# 
#              Synchronous High Speed Single Port SRAM Compiler 
# 
#                    UMC 0.18um GenericII Logic Process
#    __________________________________________________________________________
# 
# 
#      (C) Copyright 2002-2009 Faraday Technology Corp. All Rights Reserved.
#    
#    This source code is an unpublished work belongs to Faraday Technology
#    Corp.  It is considered a trade secret and is not to be divulged or
#    used by parties who have not received written authorization from
#    Faraday Technology Corp.
#    
#    Faraday's home page can be found at:
#    http://www.faraday-tech.com/
#   
#       Module Name      : SUMA180_2048X16X1BM1
#       Words            : 2048
#       Bits             : 16
#       Byte-Write       : 1
#       Aspect Ratio     : 1
#       Output Loading   : 0.05  (pf)
#       Data Slew        : 0.02  (ns)
#       CK Slew          : 0.02  (ns)
#       Power Ring Width : 2  (um)
# 
# -----------------------------------------------------------------------------
# 
#       Library          : FSA0M_A
#       Memaker          : 200901.2.1
#       Date             : 2025/11/09 15:44:09
# 
# -----------------------------------------------------------------------------


NAMESCASESENSITIVE ON ;
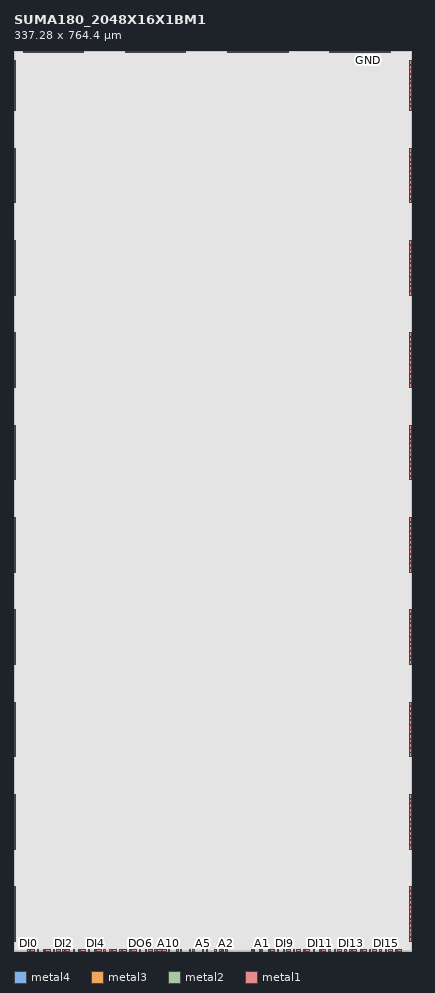
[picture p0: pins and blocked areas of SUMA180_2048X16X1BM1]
MACRO SUMA180_2048X16X1BM1
CLASS BLOCK ;
FOREIGN SUMA180_2048X16X1BM1 0.000 0.000 ;
ORIGIN 0.000 0.000 ;
SIZE 337.280 BY 764.400 ;
SYMMETRY x y r90 ;
SITE core_5040 ;
PIN VCC
  DIRECTION INOUT ;
  USE POWER ;
  SHAPE ABUTMENT ;
 PORT
  LAYER metal4 ;
  RECT 336.160 752.980 337.280 756.220 ;
  LAYER metal3 ;
  RECT 336.160 752.980 337.280 756.220 ;
  LAYER metal2 ;
  RECT 336.160 752.980 337.280 756.220 ;
  LAYER metal1 ;
  RECT 336.160 752.980 337.280 756.220 ;
 END
 PORT
  LAYER metal4 ;
  RECT 336.160 745.140 337.280 748.380 ;
  LAYER metal3 ;
  RECT 336.160 745.140 337.280 748.380 ;
  LAYER metal2 ;
  RECT 336.160 745.140 337.280 748.380 ;
  LAYER metal1 ;
  RECT 336.160 745.140 337.280 748.380 ;
 END
 PORT
  LAYER metal4 ;
  RECT 336.160 737.300 337.280 740.540 ;
  LAYER metal3 ;
  RECT 336.160 737.300 337.280 740.540 ;
  LAYER metal2 ;
  RECT 336.160 737.300 337.280 740.540 ;
  LAYER metal1 ;
  RECT 336.160 737.300 337.280 740.540 ;
 END
 PORT
  LAYER metal4 ;
  RECT 336.160 729.460 337.280 732.700 ;
  LAYER metal3 ;
  RECT 336.160 729.460 337.280 732.700 ;
  LAYER metal2 ;
  RECT 336.160 729.460 337.280 732.700 ;
  LAYER metal1 ;
  RECT 336.160 729.460 337.280 732.700 ;
 END
 PORT
  LAYER metal4 ;
  RECT 336.160 721.620 337.280 724.860 ;
  LAYER metal3 ;
  RECT 336.160 721.620 337.280 724.860 ;
  LAYER metal2 ;
  RECT 336.160 721.620 337.280 724.860 ;
  LAYER metal1 ;
  RECT 336.160 721.620 337.280 724.860 ;
 END
 PORT
  LAYER metal4 ;
  RECT 336.160 713.780 337.280 717.020 ;
  LAYER metal3 ;
  RECT 336.160 713.780 337.280 717.020 ;
  LAYER metal2 ;
  RECT 336.160 713.780 337.280 717.020 ;
  LAYER metal1 ;
  RECT 336.160 713.780 337.280 717.020 ;
 END
 PORT
  LAYER metal4 ;
  RECT 336.160 674.580 337.280 677.820 ;
  LAYER metal3 ;
  RECT 336.160 674.580 337.280 677.820 ;
  LAYER metal2 ;
  RECT 336.160 674.580 337.280 677.820 ;
  LAYER metal1 ;
  RECT 336.160 674.580 337.280 677.820 ;
 END
 PORT
  LAYER metal4 ;
  RECT 336.160 666.740 337.280 669.980 ;
  LAYER metal3 ;
  RECT 336.160 666.740 337.280 669.980 ;
  LAYER metal2 ;
  RECT 336.160 666.740 337.280 669.980 ;
  LAYER metal1 ;
  RECT 336.160 666.740 337.280 669.980 ;
 END
 PORT
  LAYER metal4 ;
  RECT 336.160 658.900 337.280 662.140 ;
  LAYER metal3 ;
  RECT 336.160 658.900 337.280 662.140 ;
  LAYER metal2 ;
  RECT 336.160 658.900 337.280 662.140 ;
  LAYER metal1 ;
  RECT 336.160 658.900 337.280 662.140 ;
 END
 PORT
  LAYER metal4 ;
  RECT 336.160 651.060 337.280 654.300 ;
  LAYER metal3 ;
  RECT 336.160 651.060 337.280 654.300 ;
  LAYER metal2 ;
  RECT 336.160 651.060 337.280 654.300 ;
  LAYER metal1 ;
  RECT 336.160 651.060 337.280 654.300 ;
 END
 PORT
  LAYER metal4 ;
  RECT 336.160 643.220 337.280 646.460 ;
  LAYER metal3 ;
  RECT 336.160 643.220 337.280 646.460 ;
  LAYER metal2 ;
  RECT 336.160 643.220 337.280 646.460 ;
  LAYER metal1 ;
  RECT 336.160 643.220 337.280 646.460 ;
 END
 PORT
  LAYER metal4 ;
  RECT 336.160 635.380 337.280 638.620 ;
  LAYER metal3 ;
  RECT 336.160 635.380 337.280 638.620 ;
  LAYER metal2 ;
  RECT 336.160 635.380 337.280 638.620 ;
  LAYER metal1 ;
  RECT 336.160 635.380 337.280 638.620 ;
 END
 PORT
  LAYER metal4 ;
  RECT 336.160 596.180 337.280 599.420 ;
  LAYER metal3 ;
  RECT 336.160 596.180 337.280 599.420 ;
  LAYER metal2 ;
  RECT 336.160 596.180 337.280 599.420 ;
  LAYER metal1 ;
  RECT 336.160 596.180 337.280 599.420 ;
 END
 PORT
  LAYER metal4 ;
  RECT 336.160 588.340 337.280 591.580 ;
  LAYER metal3 ;
  RECT 336.160 588.340 337.280 591.580 ;
  LAYER metal2 ;
  RECT 336.160 588.340 337.280 591.580 ;
  LAYER metal1 ;
  RECT 336.160 588.340 337.280 591.580 ;
 END
 PORT
  LAYER metal4 ;
  RECT 336.160 580.500 337.280 583.740 ;
  LAYER metal3 ;
  RECT 336.160 580.500 337.280 583.740 ;
  LAYER metal2 ;
  RECT 336.160 580.500 337.280 583.740 ;
  LAYER metal1 ;
  RECT 336.160 580.500 337.280 583.740 ;
 END
 PORT
  LAYER metal4 ;
  RECT 336.160 572.660 337.280 575.900 ;
  LAYER metal3 ;
  RECT 336.160 572.660 337.280 575.900 ;
  LAYER metal2 ;
  RECT 336.160 572.660 337.280 575.900 ;
  LAYER metal1 ;
  RECT 336.160 572.660 337.280 575.900 ;
 END
 PORT
  LAYER metal4 ;
  RECT 336.160 564.820 337.280 568.060 ;
  LAYER metal3 ;
  RECT 336.160 564.820 337.280 568.060 ;
  LAYER metal2 ;
  RECT 336.160 564.820 337.280 568.060 ;
  LAYER metal1 ;
  RECT 336.160 564.820 337.280 568.060 ;
 END
 PORT
  LAYER metal4 ;
  RECT 336.160 556.980 337.280 560.220 ;
  LAYER metal3 ;
  RECT 336.160 556.980 337.280 560.220 ;
  LAYER metal2 ;
  RECT 336.160 556.980 337.280 560.220 ;
  LAYER metal1 ;
  RECT 336.160 556.980 337.280 560.220 ;
 END
 PORT
  LAYER metal4 ;
  RECT 336.160 517.780 337.280 521.020 ;
  LAYER metal3 ;
  RECT 336.160 517.780 337.280 521.020 ;
  LAYER metal2 ;
  RECT 336.160 517.780 337.280 521.020 ;
  LAYER metal1 ;
  RECT 336.160 517.780 337.280 521.020 ;
 END
 PORT
  LAYER metal4 ;
  RECT 336.160 509.940 337.280 513.180 ;
  LAYER metal3 ;
  RECT 336.160 509.940 337.280 513.180 ;
  LAYER metal2 ;
  RECT 336.160 509.940 337.280 513.180 ;
  LAYER metal1 ;
  RECT 336.160 509.940 337.280 513.180 ;
 END
 PORT
  LAYER metal4 ;
  RECT 336.160 502.100 337.280 505.340 ;
  LAYER metal3 ;
  RECT 336.160 502.100 337.280 505.340 ;
  LAYER metal2 ;
  RECT 336.160 502.100 337.280 505.340 ;
  LAYER metal1 ;
  RECT 336.160 502.100 337.280 505.340 ;
 END
 PORT
  LAYER metal4 ;
  RECT 336.160 494.260 337.280 497.500 ;
  LAYER metal3 ;
  RECT 336.160 494.260 337.280 497.500 ;
  LAYER metal2 ;
  RECT 336.160 494.260 337.280 497.500 ;
  LAYER metal1 ;
  RECT 336.160 494.260 337.280 497.500 ;
 END
 PORT
  LAYER metal4 ;
  RECT 336.160 486.420 337.280 489.660 ;
  LAYER metal3 ;
  RECT 336.160 486.420 337.280 489.660 ;
  LAYER metal2 ;
  RECT 336.160 486.420 337.280 489.660 ;
  LAYER metal1 ;
  RECT 336.160 486.420 337.280 489.660 ;
 END
 PORT
  LAYER metal4 ;
  RECT 336.160 478.580 337.280 481.820 ;
  LAYER metal3 ;
  RECT 336.160 478.580 337.280 481.820 ;
  LAYER metal2 ;
  RECT 336.160 478.580 337.280 481.820 ;
  LAYER metal1 ;
  RECT 336.160 478.580 337.280 481.820 ;
 END
 PORT
  LAYER metal4 ;
  RECT 336.160 439.380 337.280 442.620 ;
  LAYER metal3 ;
  RECT 336.160 439.380 337.280 442.620 ;
  LAYER metal2 ;
  RECT 336.160 439.380 337.280 442.620 ;
  LAYER metal1 ;
  RECT 336.160 439.380 337.280 442.620 ;
 END
 PORT
  LAYER metal4 ;
  RECT 336.160 431.540 337.280 434.780 ;
  LAYER metal3 ;
  RECT 336.160 431.540 337.280 434.780 ;
  LAYER metal2 ;
  RECT 336.160 431.540 337.280 434.780 ;
  LAYER metal1 ;
  RECT 336.160 431.540 337.280 434.780 ;
 END
 PORT
  LAYER metal4 ;
  RECT 336.160 423.700 337.280 426.940 ;
  LAYER metal3 ;
  RECT 336.160 423.700 337.280 426.940 ;
  LAYER metal2 ;
  RECT 336.160 423.700 337.280 426.940 ;
  LAYER metal1 ;
  RECT 336.160 423.700 337.280 426.940 ;
 END
 PORT
  LAYER metal4 ;
  RECT 336.160 415.860 337.280 419.100 ;
  LAYER metal3 ;
  RECT 336.160 415.860 337.280 419.100 ;
  LAYER metal2 ;
  RECT 336.160 415.860 337.280 419.100 ;
  LAYER metal1 ;
  RECT 336.160 415.860 337.280 419.100 ;
 END
 PORT
  LAYER metal4 ;
  RECT 336.160 408.020 337.280 411.260 ;
  LAYER metal3 ;
  RECT 336.160 408.020 337.280 411.260 ;
  LAYER metal2 ;
  RECT 336.160 408.020 337.280 411.260 ;
  LAYER metal1 ;
  RECT 336.160 408.020 337.280 411.260 ;
 END
 PORT
  LAYER metal4 ;
  RECT 336.160 400.180 337.280 403.420 ;
  LAYER metal3 ;
  RECT 336.160 400.180 337.280 403.420 ;
  LAYER metal2 ;
  RECT 336.160 400.180 337.280 403.420 ;
  LAYER metal1 ;
  RECT 336.160 400.180 337.280 403.420 ;
 END
 PORT
  LAYER metal4 ;
  RECT 336.160 360.980 337.280 364.220 ;
  LAYER metal3 ;
  RECT 336.160 360.980 337.280 364.220 ;
  LAYER metal2 ;
  RECT 336.160 360.980 337.280 364.220 ;
  LAYER metal1 ;
  RECT 336.160 360.980 337.280 364.220 ;
 END
 PORT
  LAYER metal4 ;
  RECT 336.160 353.140 337.280 356.380 ;
  LAYER metal3 ;
  RECT 336.160 353.140 337.280 356.380 ;
  LAYER metal2 ;
  RECT 336.160 353.140 337.280 356.380 ;
  LAYER metal1 ;
  RECT 336.160 353.140 337.280 356.380 ;
 END
 PORT
  LAYER metal4 ;
  RECT 336.160 345.300 337.280 348.540 ;
  LAYER metal3 ;
  RECT 336.160 345.300 337.280 348.540 ;
  LAYER metal2 ;
  RECT 336.160 345.300 337.280 348.540 ;
  LAYER metal1 ;
  RECT 336.160 345.300 337.280 348.540 ;
 END
 PORT
  LAYER metal4 ;
  RECT 336.160 337.460 337.280 340.700 ;
  LAYER metal3 ;
  RECT 336.160 337.460 337.280 340.700 ;
  LAYER metal2 ;
  RECT 336.160 337.460 337.280 340.700 ;
  LAYER metal1 ;
  RECT 336.160 337.460 337.280 340.700 ;
 END
 PORT
  LAYER metal4 ;
  RECT 336.160 329.620 337.280 332.860 ;
  LAYER metal3 ;
  RECT 336.160 329.620 337.280 332.860 ;
  LAYER metal2 ;
  RECT 336.160 329.620 337.280 332.860 ;
  LAYER metal1 ;
  RECT 336.160 329.620 337.280 332.860 ;
 END
 PORT
  LAYER metal4 ;
  RECT 336.160 321.780 337.280 325.020 ;
  LAYER metal3 ;
  RECT 336.160 321.780 337.280 325.020 ;
  LAYER metal2 ;
  RECT 336.160 321.780 337.280 325.020 ;
  LAYER metal1 ;
  RECT 336.160 321.780 337.280 325.020 ;
 END
 PORT
  LAYER metal4 ;
  RECT 336.160 282.580 337.280 285.820 ;
  LAYER metal3 ;
  RECT 336.160 282.580 337.280 285.820 ;
  LAYER metal2 ;
  RECT 336.160 282.580 337.280 285.820 ;
  LAYER metal1 ;
  RECT 336.160 282.580 337.280 285.820 ;
 END
 PORT
  LAYER metal4 ;
  RECT 336.160 274.740 337.280 277.980 ;
  LAYER metal3 ;
  RECT 336.160 274.740 337.280 277.980 ;
  LAYER metal2 ;
  RECT 336.160 274.740 337.280 277.980 ;
  LAYER metal1 ;
  RECT 336.160 274.740 337.280 277.980 ;
 END
 PORT
  LAYER metal4 ;
  RECT 336.160 266.900 337.280 270.140 ;
  LAYER metal3 ;
  RECT 336.160 266.900 337.280 270.140 ;
  LAYER metal2 ;
  RECT 336.160 266.900 337.280 270.140 ;
  LAYER metal1 ;
  RECT 336.160 266.900 337.280 270.140 ;
 END
 PORT
  LAYER metal4 ;
  RECT 336.160 259.060 337.280 262.300 ;
  LAYER metal3 ;
  RECT 336.160 259.060 337.280 262.300 ;
  LAYER metal2 ;
  RECT 336.160 259.060 337.280 262.300 ;
  LAYER metal1 ;
  RECT 336.160 259.060 337.280 262.300 ;
 END
 PORT
  LAYER metal4 ;
  RECT 336.160 251.220 337.280 254.460 ;
  LAYER metal3 ;
  RECT 336.160 251.220 337.280 254.460 ;
  LAYER metal2 ;
  RECT 336.160 251.220 337.280 254.460 ;
  LAYER metal1 ;
  RECT 336.160 251.220 337.280 254.460 ;
 END
 PORT
  LAYER metal4 ;
  RECT 336.160 243.380 337.280 246.620 ;
  LAYER metal3 ;
  RECT 336.160 243.380 337.280 246.620 ;
  LAYER metal2 ;
  RECT 336.160 243.380 337.280 246.620 ;
  LAYER metal1 ;
  RECT 336.160 243.380 337.280 246.620 ;
 END
 PORT
  LAYER metal4 ;
  RECT 336.160 204.180 337.280 207.420 ;
  LAYER metal3 ;
  RECT 336.160 204.180 337.280 207.420 ;
  LAYER metal2 ;
  RECT 336.160 204.180 337.280 207.420 ;
  LAYER metal1 ;
  RECT 336.160 204.180 337.280 207.420 ;
 END
 PORT
  LAYER metal4 ;
  RECT 336.160 196.340 337.280 199.580 ;
  LAYER metal3 ;
  RECT 336.160 196.340 337.280 199.580 ;
  LAYER metal2 ;
  RECT 336.160 196.340 337.280 199.580 ;
  LAYER metal1 ;
  RECT 336.160 196.340 337.280 199.580 ;
 END
 PORT
  LAYER metal4 ;
  RECT 336.160 188.500 337.280 191.740 ;
  LAYER metal3 ;
  RECT 336.160 188.500 337.280 191.740 ;
  LAYER metal2 ;
  RECT 336.160 188.500 337.280 191.740 ;
  LAYER metal1 ;
  RECT 336.160 188.500 337.280 191.740 ;
 END
 PORT
  LAYER metal4 ;
  RECT 336.160 180.660 337.280 183.900 ;
  LAYER metal3 ;
  RECT 336.160 180.660 337.280 183.900 ;
  LAYER metal2 ;
  RECT 336.160 180.660 337.280 183.900 ;
  LAYER metal1 ;
  RECT 336.160 180.660 337.280 183.900 ;
 END
 PORT
  LAYER metal4 ;
  RECT 336.160 172.820 337.280 176.060 ;
  LAYER metal3 ;
  RECT 336.160 172.820 337.280 176.060 ;
  LAYER metal2 ;
  RECT 336.160 172.820 337.280 176.060 ;
  LAYER metal1 ;
  RECT 336.160 172.820 337.280 176.060 ;
 END
 PORT
  LAYER metal4 ;
  RECT 336.160 164.980 337.280 168.220 ;
  LAYER metal3 ;
  RECT 336.160 164.980 337.280 168.220 ;
  LAYER metal2 ;
  RECT 336.160 164.980 337.280 168.220 ;
  LAYER metal1 ;
  RECT 336.160 164.980 337.280 168.220 ;
 END
 PORT
  LAYER metal4 ;
  RECT 336.160 125.780 337.280 129.020 ;
  LAYER metal3 ;
  RECT 336.160 125.780 337.280 129.020 ;
  LAYER metal2 ;
  RECT 336.160 125.780 337.280 129.020 ;
  LAYER metal1 ;
  RECT 336.160 125.780 337.280 129.020 ;
 END
 PORT
  LAYER metal4 ;
  RECT 336.160 117.940 337.280 121.180 ;
  LAYER metal3 ;
  RECT 336.160 117.940 337.280 121.180 ;
  LAYER metal2 ;
  RECT 336.160 117.940 337.280 121.180 ;
  LAYER metal1 ;
  RECT 336.160 117.940 337.280 121.180 ;
 END
 PORT
  LAYER metal4 ;
  RECT 336.160 110.100 337.280 113.340 ;
  LAYER metal3 ;
  RECT 336.160 110.100 337.280 113.340 ;
  LAYER metal2 ;
  RECT 336.160 110.100 337.280 113.340 ;
  LAYER metal1 ;
  RECT 336.160 110.100 337.280 113.340 ;
 END
 PORT
  LAYER metal4 ;
  RECT 336.160 102.260 337.280 105.500 ;
  LAYER metal3 ;
  RECT 336.160 102.260 337.280 105.500 ;
  LAYER metal2 ;
  RECT 336.160 102.260 337.280 105.500 ;
  LAYER metal1 ;
  RECT 336.160 102.260 337.280 105.500 ;
 END
 PORT
  LAYER metal4 ;
  RECT 336.160 94.420 337.280 97.660 ;
  LAYER metal3 ;
  RECT 336.160 94.420 337.280 97.660 ;
  LAYER metal2 ;
  RECT 336.160 94.420 337.280 97.660 ;
  LAYER metal1 ;
  RECT 336.160 94.420 337.280 97.660 ;
 END
 PORT
  LAYER metal4 ;
  RECT 336.160 86.580 337.280 89.820 ;
  LAYER metal3 ;
  RECT 336.160 86.580 337.280 89.820 ;
  LAYER metal2 ;
  RECT 336.160 86.580 337.280 89.820 ;
  LAYER metal1 ;
  RECT 336.160 86.580 337.280 89.820 ;
 END
 PORT
  LAYER metal4 ;
  RECT 336.160 47.380 337.280 50.620 ;
  LAYER metal3 ;
  RECT 336.160 47.380 337.280 50.620 ;
  LAYER metal2 ;
  RECT 336.160 47.380 337.280 50.620 ;
  LAYER metal1 ;
  RECT 336.160 47.380 337.280 50.620 ;
 END
 PORT
  LAYER metal4 ;
  RECT 336.160 39.540 337.280 42.780 ;
  LAYER metal3 ;
  RECT 336.160 39.540 337.280 42.780 ;
  LAYER metal2 ;
  RECT 336.160 39.540 337.280 42.780 ;
  LAYER metal1 ;
  RECT 336.160 39.540 337.280 42.780 ;
 END
 PORT
  LAYER metal4 ;
  RECT 336.160 31.700 337.280 34.940 ;
  LAYER metal3 ;
  RECT 336.160 31.700 337.280 34.940 ;
  LAYER metal2 ;
  RECT 336.160 31.700 337.280 34.940 ;
  LAYER metal1 ;
  RECT 336.160 31.700 337.280 34.940 ;
 END
 PORT
  LAYER metal4 ;
  RECT 336.160 23.860 337.280 27.100 ;
  LAYER metal3 ;
  RECT 336.160 23.860 337.280 27.100 ;
  LAYER metal2 ;
  RECT 336.160 23.860 337.280 27.100 ;
  LAYER metal1 ;
  RECT 336.160 23.860 337.280 27.100 ;
 END
 PORT
  LAYER metal4 ;
  RECT 336.160 16.020 337.280 19.260 ;
  LAYER metal3 ;
  RECT 336.160 16.020 337.280 19.260 ;
  LAYER metal2 ;
  RECT 336.160 16.020 337.280 19.260 ;
  LAYER metal1 ;
  RECT 336.160 16.020 337.280 19.260 ;
 END
 PORT
  LAYER metal4 ;
  RECT 336.160 8.180 337.280 11.420 ;
  LAYER metal3 ;
  RECT 336.160 8.180 337.280 11.420 ;
  LAYER metal2 ;
  RECT 336.160 8.180 337.280 11.420 ;
  LAYER metal1 ;
  RECT 336.160 8.180 337.280 11.420 ;
 END
 PORT
  LAYER metal4 ;
  RECT 0.000 752.980 1.120 756.220 ;
  LAYER metal3 ;
  RECT 0.000 752.980 1.120 756.220 ;
  LAYER metal2 ;
  RECT 0.000 752.980 1.120 756.220 ;
  LAYER metal1 ;
  RECT 0.000 752.980 1.120 756.220 ;
 END
 PORT
  LAYER metal4 ;
  RECT 0.000 745.140 1.120 748.380 ;
  LAYER metal3 ;
  RECT 0.000 745.140 1.120 748.380 ;
  LAYER metal2 ;
  RECT 0.000 745.140 1.120 748.380 ;
  LAYER metal1 ;
  RECT 0.000 745.140 1.120 748.380 ;
 END
 PORT
  LAYER metal4 ;
  RECT 0.000 737.300 1.120 740.540 ;
  LAYER metal3 ;
  RECT 0.000 737.300 1.120 740.540 ;
  LAYER metal2 ;
  RECT 0.000 737.300 1.120 740.540 ;
  LAYER metal1 ;
  RECT 0.000 737.300 1.120 740.540 ;
 END
 PORT
  LAYER metal4 ;
  RECT 0.000 729.460 1.120 732.700 ;
  LAYER metal3 ;
  RECT 0.000 729.460 1.120 732.700 ;
  LAYER metal2 ;
  RECT 0.000 729.460 1.120 732.700 ;
  LAYER metal1 ;
  RECT 0.000 729.460 1.120 732.700 ;
 END
 PORT
  LAYER metal4 ;
  RECT 0.000 721.620 1.120 724.860 ;
  LAYER metal3 ;
  RECT 0.000 721.620 1.120 724.860 ;
  LAYER metal2 ;
  RECT 0.000 721.620 1.120 724.860 ;
  LAYER metal1 ;
  RECT 0.000 721.620 1.120 724.860 ;
 END
 PORT
  LAYER metal4 ;
  RECT 0.000 713.780 1.120 717.020 ;
  LAYER metal3 ;
  RECT 0.000 713.780 1.120 717.020 ;
  LAYER metal2 ;
  RECT 0.000 713.780 1.120 717.020 ;
  LAYER metal1 ;
  RECT 0.000 713.780 1.120 717.020 ;
 END
 PORT
  LAYER metal4 ;
  RECT 0.000 674.580 1.120 677.820 ;
  LAYER metal3 ;
  RECT 0.000 674.580 1.120 677.820 ;
  LAYER metal2 ;
  RECT 0.000 674.580 1.120 677.820 ;
  LAYER metal1 ;
  RECT 0.000 674.580 1.120 677.820 ;
 END
 PORT
  LAYER metal4 ;
  RECT 0.000 666.740 1.120 669.980 ;
  LAYER metal3 ;
  RECT 0.000 666.740 1.120 669.980 ;
  LAYER metal2 ;
  RECT 0.000 666.740 1.120 669.980 ;
  LAYER metal1 ;
  RECT 0.000 666.740 1.120 669.980 ;
 END
 PORT
  LAYER metal4 ;
  RECT 0.000 658.900 1.120 662.140 ;
  LAYER metal3 ;
  RECT 0.000 658.900 1.120 662.140 ;
  LAYER metal2 ;
  RECT 0.000 658.900 1.120 662.140 ;
  LAYER metal1 ;
  RECT 0.000 658.900 1.120 662.140 ;
 END
 PORT
  LAYER metal4 ;
  RECT 0.000 651.060 1.120 654.300 ;
  LAYER metal3 ;
  RECT 0.000 651.060 1.120 654.300 ;
  LAYER metal2 ;
  RECT 0.000 651.060 1.120 654.300 ;
  LAYER metal1 ;
  RECT 0.000 651.060 1.120 654.300 ;
 END
 PORT
  LAYER metal4 ;
  RECT 0.000 643.220 1.120 646.460 ;
  LAYER metal3 ;
  RECT 0.000 643.220 1.120 646.460 ;
  LAYER metal2 ;
  RECT 0.000 643.220 1.120 646.460 ;
  LAYER metal1 ;
  RECT 0.000 643.220 1.120 646.460 ;
 END
 PORT
  LAYER metal4 ;
  RECT 0.000 635.380 1.120 638.620 ;
  LAYER metal3 ;
  RECT 0.000 635.380 1.120 638.620 ;
  LAYER metal2 ;
  RECT 0.000 635.380 1.120 638.620 ;
  LAYER metal1 ;
  RECT 0.000 635.380 1.120 638.620 ;
 END
 PORT
  LAYER metal4 ;
  RECT 0.000 596.180 1.120 599.420 ;
  LAYER metal3 ;
  RECT 0.000 596.180 1.120 599.420 ;
  LAYER metal2 ;
  RECT 0.000 596.180 1.120 599.420 ;
  LAYER metal1 ;
  RECT 0.000 596.180 1.120 599.420 ;
 END
 PORT
  LAYER metal4 ;
  RECT 0.000 588.340 1.120 591.580 ;
  LAYER metal3 ;
  RECT 0.000 588.340 1.120 591.580 ;
  LAYER metal2 ;
  RECT 0.000 588.340 1.120 591.580 ;
  LAYER metal1 ;
  RECT 0.000 588.340 1.120 591.580 ;
 END
 PORT
  LAYER metal4 ;
  RECT 0.000 580.500 1.120 583.740 ;
  LAYER metal3 ;
  RECT 0.000 580.500 1.120 583.740 ;
  LAYER metal2 ;
  RECT 0.000 580.500 1.120 583.740 ;
  LAYER metal1 ;
  RECT 0.000 580.500 1.120 583.740 ;
 END
 PORT
  LAYER metal4 ;
  RECT 0.000 572.660 1.120 575.900 ;
  LAYER metal3 ;
  RECT 0.000 572.660 1.120 575.900 ;
  LAYER metal2 ;
  RECT 0.000 572.660 1.120 575.900 ;
  LAYER metal1 ;
  RECT 0.000 572.660 1.120 575.900 ;
 END
 PORT
  LAYER metal4 ;
  RECT 0.000 564.820 1.120 568.060 ;
  LAYER metal3 ;
  RECT 0.000 564.820 1.120 568.060 ;
  LAYER metal2 ;
  RECT 0.000 564.820 1.120 568.060 ;
  LAYER metal1 ;
  RECT 0.000 564.820 1.120 568.060 ;
 END
 PORT
  LAYER metal4 ;
  RECT 0.000 556.980 1.120 560.220 ;
  LAYER metal3 ;
  RECT 0.000 556.980 1.120 560.220 ;
  LAYER metal2 ;
  RECT 0.000 556.980 1.120 560.220 ;
  LAYER metal1 ;
  RECT 0.000 556.980 1.120 560.220 ;
 END
 PORT
  LAYER metal4 ;
  RECT 0.000 517.780 1.120 521.020 ;
  LAYER metal3 ;
  RECT 0.000 517.780 1.120 521.020 ;
  LAYER metal2 ;
  RECT 0.000 517.780 1.120 521.020 ;
  LAYER metal1 ;
  RECT 0.000 517.780 1.120 521.020 ;
 END
 PORT
  LAYER metal4 ;
  RECT 0.000 509.940 1.120 513.180 ;
  LAYER metal3 ;
  RECT 0.000 509.940 1.120 513.180 ;
  LAYER metal2 ;
  RECT 0.000 509.940 1.120 513.180 ;
  LAYER metal1 ;
  RECT 0.000 509.940 1.120 513.180 ;
 END
 PORT
  LAYER metal4 ;
  RECT 0.000 502.100 1.120 505.340 ;
  LAYER metal3 ;
  RECT 0.000 502.100 1.120 505.340 ;
  LAYER metal2 ;
  RECT 0.000 502.100 1.120 505.340 ;
  LAYER metal1 ;
  RECT 0.000 502.100 1.120 505.340 ;
 END
 PORT
  LAYER metal4 ;
  RECT 0.000 494.260 1.120 497.500 ;
  LAYER metal3 ;
  RECT 0.000 494.260 1.120 497.500 ;
  LAYER metal2 ;
  RECT 0.000 494.260 1.120 497.500 ;
  LAYER metal1 ;
  RECT 0.000 494.260 1.120 497.500 ;
 END
 PORT
  LAYER metal4 ;
  RECT 0.000 486.420 1.120 489.660 ;
  LAYER metal3 ;
  RECT 0.000 486.420 1.120 489.660 ;
  LAYER metal2 ;
  RECT 0.000 486.420 1.120 489.660 ;
  LAYER metal1 ;
  RECT 0.000 486.420 1.120 489.660 ;
 END
 PORT
  LAYER metal4 ;
  RECT 0.000 478.580 1.120 481.820 ;
  LAYER metal3 ;
  RECT 0.000 478.580 1.120 481.820 ;
  LAYER metal2 ;
  RECT 0.000 478.580 1.120 481.820 ;
  LAYER metal1 ;
  RECT 0.000 478.580 1.120 481.820 ;
 END
 PORT
  LAYER metal4 ;
  RECT 0.000 439.380 1.120 442.620 ;
  LAYER metal3 ;
  RECT 0.000 439.380 1.120 442.620 ;
  LAYER metal2 ;
  RECT 0.000 439.380 1.120 442.620 ;
  LAYER metal1 ;
  RECT 0.000 439.380 1.120 442.620 ;
 END
 PORT
  LAYER metal4 ;
  RECT 0.000 431.540 1.120 434.780 ;
  LAYER metal3 ;
  RECT 0.000 431.540 1.120 434.780 ;
  LAYER metal2 ;
  RECT 0.000 431.540 1.120 434.780 ;
  LAYER metal1 ;
  RECT 0.000 431.540 1.120 434.780 ;
 END
 PORT
  LAYER metal4 ;
  RECT 0.000 423.700 1.120 426.940 ;
  LAYER metal3 ;
  RECT 0.000 423.700 1.120 426.940 ;
  LAYER metal2 ;
  RECT 0.000 423.700 1.120 426.940 ;
  LAYER metal1 ;
  RECT 0.000 423.700 1.120 426.940 ;
 END
 PORT
  LAYER metal4 ;
  RECT 0.000 415.860 1.120 419.100 ;
  LAYER metal3 ;
  RECT 0.000 415.860 1.120 419.100 ;
  LAYER metal2 ;
  RECT 0.000 415.860 1.120 419.100 ;
  LAYER metal1 ;
  RECT 0.000 415.860 1.120 419.100 ;
 END
 PORT
  LAYER metal4 ;
  RECT 0.000 408.020 1.120 411.260 ;
  LAYER metal3 ;
  RECT 0.000 408.020 1.120 411.260 ;
  LAYER metal2 ;
  RECT 0.000 408.020 1.120 411.260 ;
  LAYER metal1 ;
  RECT 0.000 408.020 1.120 411.260 ;
 END
 PORT
  LAYER metal4 ;
  RECT 0.000 400.180 1.120 403.420 ;
  LAYER metal3 ;
  RECT 0.000 400.180 1.120 403.420 ;
  LAYER metal2 ;
  RECT 0.000 400.180 1.120 403.420 ;
  LAYER metal1 ;
  RECT 0.000 400.180 1.120 403.420 ;
 END
 PORT
  LAYER metal4 ;
  RECT 0.000 360.980 1.120 364.220 ;
  LAYER metal3 ;
  RECT 0.000 360.980 1.120 364.220 ;
  LAYER metal2 ;
  RECT 0.000 360.980 1.120 364.220 ;
  LAYER metal1 ;
  RECT 0.000 360.980 1.120 364.220 ;
 END
 PORT
  LAYER metal4 ;
  RECT 0.000 353.140 1.120 356.380 ;
  LAYER metal3 ;
  RECT 0.000 353.140 1.120 356.380 ;
  LAYER metal2 ;
  RECT 0.000 353.140 1.120 356.380 ;
  LAYER metal1 ;
  RECT 0.000 353.140 1.120 356.380 ;
 END
 PORT
  LAYER metal4 ;
  RECT 0.000 345.300 1.120 348.540 ;
  LAYER metal3 ;
  RECT 0.000 345.300 1.120 348.540 ;
  LAYER metal2 ;
  RECT 0.000 345.300 1.120 348.540 ;
  LAYER metal1 ;
  RECT 0.000 345.300 1.120 348.540 ;
 END
 PORT
  LAYER metal4 ;
  RECT 0.000 337.460 1.120 340.700 ;
  LAYER metal3 ;
  RECT 0.000 337.460 1.120 340.700 ;
  LAYER metal2 ;
  RECT 0.000 337.460 1.120 340.700 ;
  LAYER metal1 ;
  RECT 0.000 337.460 1.120 340.700 ;
 END
 PORT
  LAYER metal4 ;
  RECT 0.000 329.620 1.120 332.860 ;
  LAYER metal3 ;
  RECT 0.000 329.620 1.120 332.860 ;
  LAYER metal2 ;
  RECT 0.000 329.620 1.120 332.860 ;
  LAYER metal1 ;
  RECT 0.000 329.620 1.120 332.860 ;
 END
 PORT
  LAYER metal4 ;
  RECT 0.000 321.780 1.120 325.020 ;
  LAYER metal3 ;
  RECT 0.000 321.780 1.120 325.020 ;
  LAYER metal2 ;
  RECT 0.000 321.780 1.120 325.020 ;
  LAYER metal1 ;
  RECT 0.000 321.780 1.120 325.020 ;
 END
 PORT
  LAYER metal4 ;
  RECT 0.000 282.580 1.120 285.820 ;
  LAYER metal3 ;
  RECT 0.000 282.580 1.120 285.820 ;
  LAYER metal2 ;
  RECT 0.000 282.580 1.120 285.820 ;
  LAYER metal1 ;
  RECT 0.000 282.580 1.120 285.820 ;
 END
 PORT
  LAYER metal4 ;
  RECT 0.000 274.740 1.120 277.980 ;
  LAYER metal3 ;
  RECT 0.000 274.740 1.120 277.980 ;
  LAYER metal2 ;
  RECT 0.000 274.740 1.120 277.980 ;
  LAYER metal1 ;
  RECT 0.000 274.740 1.120 277.980 ;
 END
 PORT
  LAYER metal4 ;
  RECT 0.000 266.900 1.120 270.140 ;
  LAYER metal3 ;
  RECT 0.000 266.900 1.120 270.140 ;
  LAYER metal2 ;
  RECT 0.000 266.900 1.120 270.140 ;
  LAYER metal1 ;
  RECT 0.000 266.900 1.120 270.140 ;
 END
 PORT
  LAYER metal4 ;
  RECT 0.000 259.060 1.120 262.300 ;
  LAYER metal3 ;
  RECT 0.000 259.060 1.120 262.300 ;
  LAYER metal2 ;
  RECT 0.000 259.060 1.120 262.300 ;
  LAYER metal1 ;
  RECT 0.000 259.060 1.120 262.300 ;
 END
 PORT
  LAYER metal4 ;
  RECT 0.000 251.220 1.120 254.460 ;
  LAYER metal3 ;
  RECT 0.000 251.220 1.120 254.460 ;
  LAYER metal2 ;
  RECT 0.000 251.220 1.120 254.460 ;
  LAYER metal1 ;
  RECT 0.000 251.220 1.120 254.460 ;
 END
 PORT
  LAYER metal4 ;
  RECT 0.000 243.380 1.120 246.620 ;
  LAYER metal3 ;
  RECT 0.000 243.380 1.120 246.620 ;
  LAYER metal2 ;
  RECT 0.000 243.380 1.120 246.620 ;
  LAYER metal1 ;
  RECT 0.000 243.380 1.120 246.620 ;
 END
 PORT
  LAYER metal4 ;
  RECT 0.000 204.180 1.120 207.420 ;
  LAYER metal3 ;
  RECT 0.000 204.180 1.120 207.420 ;
  LAYER metal2 ;
  RECT 0.000 204.180 1.120 207.420 ;
  LAYER metal1 ;
  RECT 0.000 204.180 1.120 207.420 ;
 END
 PORT
  LAYER metal4 ;
  RECT 0.000 196.340 1.120 199.580 ;
  LAYER metal3 ;
  RECT 0.000 196.340 1.120 199.580 ;
  LAYER metal2 ;
  RECT 0.000 196.340 1.120 199.580 ;
  LAYER metal1 ;
  RECT 0.000 196.340 1.120 199.580 ;
 END
 PORT
  LAYER metal4 ;
  RECT 0.000 188.500 1.120 191.740 ;
  LAYER metal3 ;
  RECT 0.000 188.500 1.120 191.740 ;
  LAYER metal2 ;
  RECT 0.000 188.500 1.120 191.740 ;
  LAYER metal1 ;
  RECT 0.000 188.500 1.120 191.740 ;
 END
 PORT
  LAYER metal4 ;
  RECT 0.000 180.660 1.120 183.900 ;
  LAYER metal3 ;
  RECT 0.000 180.660 1.120 183.900 ;
  LAYER metal2 ;
  RECT 0.000 180.660 1.120 183.900 ;
  LAYER metal1 ;
  RECT 0.000 180.660 1.120 183.900 ;
 END
 PORT
  LAYER metal4 ;
  RECT 0.000 172.820 1.120 176.060 ;
  LAYER metal3 ;
  RECT 0.000 172.820 1.120 176.060 ;
  LAYER metal2 ;
  RECT 0.000 172.820 1.120 176.060 ;
  LAYER metal1 ;
  RECT 0.000 172.820 1.120 176.060 ;
 END
 PORT
  LAYER metal4 ;
  RECT 0.000 164.980 1.120 168.220 ;
  LAYER metal3 ;
  RECT 0.000 164.980 1.120 168.220 ;
  LAYER metal2 ;
  RECT 0.000 164.980 1.120 168.220 ;
  LAYER metal1 ;
  RECT 0.000 164.980 1.120 168.220 ;
 END
 PORT
  LAYER metal4 ;
  RECT 0.000 125.780 1.120 129.020 ;
  LAYER metal3 ;
  RECT 0.000 125.780 1.120 129.020 ;
  LAYER metal2 ;
  RECT 0.000 125.780 1.120 129.020 ;
  LAYER metal1 ;
  RECT 0.000 125.780 1.120 129.020 ;
 END
 PORT
  LAYER metal4 ;
  RECT 0.000 117.940 1.120 121.180 ;
  LAYER metal3 ;
  RECT 0.000 117.940 1.120 121.180 ;
  LAYER metal2 ;
  RECT 0.000 117.940 1.120 121.180 ;
  LAYER metal1 ;
  RECT 0.000 117.940 1.120 121.180 ;
 END
 PORT
  LAYER metal4 ;
  RECT 0.000 110.100 1.120 113.340 ;
  LAYER metal3 ;
  RECT 0.000 110.100 1.120 113.340 ;
  LAYER metal2 ;
  RECT 0.000 110.100 1.120 113.340 ;
  LAYER metal1 ;
  RECT 0.000 110.100 1.120 113.340 ;
 END
 PORT
  LAYER metal4 ;
  RECT 0.000 102.260 1.120 105.500 ;
  LAYER metal3 ;
  RECT 0.000 102.260 1.120 105.500 ;
  LAYER metal2 ;
  RECT 0.000 102.260 1.120 105.500 ;
  LAYER metal1 ;
  RECT 0.000 102.260 1.120 105.500 ;
 END
 PORT
  LAYER metal4 ;
  RECT 0.000 94.420 1.120 97.660 ;
  LAYER metal3 ;
  RECT 0.000 94.420 1.120 97.660 ;
  LAYER metal2 ;
  RECT 0.000 94.420 1.120 97.660 ;
  LAYER metal1 ;
  RECT 0.000 94.420 1.120 97.660 ;
 END
 PORT
  LAYER metal4 ;
  RECT 0.000 86.580 1.120 89.820 ;
  LAYER metal3 ;
  RECT 0.000 86.580 1.120 89.820 ;
  LAYER metal2 ;
  RECT 0.000 86.580 1.120 89.820 ;
  LAYER metal1 ;
  RECT 0.000 86.580 1.120 89.820 ;
 END
 PORT
  LAYER metal4 ;
  RECT 0.000 47.380 1.120 50.620 ;
  LAYER metal3 ;
  RECT 0.000 47.380 1.120 50.620 ;
  LAYER metal2 ;
  RECT 0.000 47.380 1.120 50.620 ;
  LAYER metal1 ;
  RECT 0.000 47.380 1.120 50.620 ;
 END
 PORT
  LAYER metal4 ;
  RECT 0.000 39.540 1.120 42.780 ;
  LAYER metal3 ;
  RECT 0.000 39.540 1.120 42.780 ;
  LAYER metal2 ;
  RECT 0.000 39.540 1.120 42.780 ;
  LAYER metal1 ;
  RECT 0.000 39.540 1.120 42.780 ;
 END
 PORT
  LAYER metal4 ;
  RECT 0.000 31.700 1.120 34.940 ;
  LAYER metal3 ;
  RECT 0.000 31.700 1.120 34.940 ;
  LAYER metal2 ;
  RECT 0.000 31.700 1.120 34.940 ;
  LAYER metal1 ;
  RECT 0.000 31.700 1.120 34.940 ;
 END
 PORT
  LAYER metal4 ;
  RECT 0.000 23.860 1.120 27.100 ;
  LAYER metal3 ;
  RECT 0.000 23.860 1.120 27.100 ;
  LAYER metal2 ;
  RECT 0.000 23.860 1.120 27.100 ;
  LAYER metal1 ;
  RECT 0.000 23.860 1.120 27.100 ;
 END
 PORT
  LAYER metal4 ;
  RECT 0.000 16.020 1.120 19.260 ;
  LAYER metal3 ;
  RECT 0.000 16.020 1.120 19.260 ;
  LAYER metal2 ;
  RECT 0.000 16.020 1.120 19.260 ;
  LAYER metal1 ;
  RECT 0.000 16.020 1.120 19.260 ;
 END
 PORT
  LAYER metal4 ;
  RECT 0.000 8.180 1.120 11.420 ;
  LAYER metal3 ;
  RECT 0.000 8.180 1.120 11.420 ;
  LAYER metal2 ;
  RECT 0.000 8.180 1.120 11.420 ;
  LAYER metal1 ;
  RECT 0.000 8.180 1.120 11.420 ;
 END
 PORT
  LAYER metal4 ;
  RECT 311.640 763.280 315.180 764.400 ;
  LAYER metal3 ;
  RECT 311.640 763.280 315.180 764.400 ;
  LAYER metal2 ;
  RECT 311.640 763.280 315.180 764.400 ;
  LAYER metal1 ;
  RECT 311.640 763.280 315.180 764.400 ;
 END
 PORT
  LAYER metal4 ;
  RECT 302.960 763.280 306.500 764.400 ;
  LAYER metal3 ;
  RECT 302.960 763.280 306.500 764.400 ;
  LAYER metal2 ;
  RECT 302.960 763.280 306.500 764.400 ;
  LAYER metal1 ;
  RECT 302.960 763.280 306.500 764.400 ;
 END
 PORT
  LAYER metal4 ;
  RECT 294.280 763.280 297.820 764.400 ;
  LAYER metal3 ;
  RECT 294.280 763.280 297.820 764.400 ;
  LAYER metal2 ;
  RECT 294.280 763.280 297.820 764.400 ;
  LAYER metal1 ;
  RECT 294.280 763.280 297.820 764.400 ;
 END
 PORT
  LAYER metal4 ;
  RECT 285.600 763.280 289.140 764.400 ;
  LAYER metal3 ;
  RECT 285.600 763.280 289.140 764.400 ;
  LAYER metal2 ;
  RECT 285.600 763.280 289.140 764.400 ;
  LAYER metal1 ;
  RECT 285.600 763.280 289.140 764.400 ;
 END
 PORT
  LAYER metal4 ;
  RECT 276.920 763.280 280.460 764.400 ;
  LAYER metal3 ;
  RECT 276.920 763.280 280.460 764.400 ;
  LAYER metal2 ;
  RECT 276.920 763.280 280.460 764.400 ;
  LAYER metal1 ;
  RECT 276.920 763.280 280.460 764.400 ;
 END
 PORT
  LAYER metal4 ;
  RECT 268.240 763.280 271.780 764.400 ;
  LAYER metal3 ;
  RECT 268.240 763.280 271.780 764.400 ;
  LAYER metal2 ;
  RECT 268.240 763.280 271.780 764.400 ;
  LAYER metal1 ;
  RECT 268.240 763.280 271.780 764.400 ;
 END
 PORT
  LAYER metal4 ;
  RECT 224.840 763.280 228.380 764.400 ;
  LAYER metal3 ;
  RECT 224.840 763.280 228.380 764.400 ;
  LAYER metal2 ;
  RECT 224.840 763.280 228.380 764.400 ;
  LAYER metal1 ;
  RECT 224.840 763.280 228.380 764.400 ;
 END
 PORT
  LAYER metal4 ;
  RECT 216.160 763.280 219.700 764.400 ;
  LAYER metal3 ;
  RECT 216.160 763.280 219.700 764.400 ;
  LAYER metal2 ;
  RECT 216.160 763.280 219.700 764.400 ;
  LAYER metal1 ;
  RECT 216.160 763.280 219.700 764.400 ;
 END
 PORT
  LAYER metal4 ;
  RECT 207.480 763.280 211.020 764.400 ;
  LAYER metal3 ;
  RECT 207.480 763.280 211.020 764.400 ;
  LAYER metal2 ;
  RECT 207.480 763.280 211.020 764.400 ;
  LAYER metal1 ;
  RECT 207.480 763.280 211.020 764.400 ;
 END
 PORT
  LAYER metal4 ;
  RECT 198.800 763.280 202.340 764.400 ;
  LAYER metal3 ;
  RECT 198.800 763.280 202.340 764.400 ;
  LAYER metal2 ;
  RECT 198.800 763.280 202.340 764.400 ;
  LAYER metal1 ;
  RECT 198.800 763.280 202.340 764.400 ;
 END
 PORT
  LAYER metal4 ;
  RECT 190.120 763.280 193.660 764.400 ;
  LAYER metal3 ;
  RECT 190.120 763.280 193.660 764.400 ;
  LAYER metal2 ;
  RECT 190.120 763.280 193.660 764.400 ;
  LAYER metal1 ;
  RECT 190.120 763.280 193.660 764.400 ;
 END
 PORT
  LAYER metal4 ;
  RECT 181.440 763.280 184.980 764.400 ;
  LAYER metal3 ;
  RECT 181.440 763.280 184.980 764.400 ;
  LAYER metal2 ;
  RECT 181.440 763.280 184.980 764.400 ;
  LAYER metal1 ;
  RECT 181.440 763.280 184.980 764.400 ;
 END
 PORT
  LAYER metal4 ;
  RECT 138.040 763.280 141.580 764.400 ;
  LAYER metal3 ;
  RECT 138.040 763.280 141.580 764.400 ;
  LAYER metal2 ;
  RECT 138.040 763.280 141.580 764.400 ;
  LAYER metal1 ;
  RECT 138.040 763.280 141.580 764.400 ;
 END
 PORT
  LAYER metal4 ;
  RECT 129.360 763.280 132.900 764.400 ;
  LAYER metal3 ;
  RECT 129.360 763.280 132.900 764.400 ;
  LAYER metal2 ;
  RECT 129.360 763.280 132.900 764.400 ;
  LAYER metal1 ;
  RECT 129.360 763.280 132.900 764.400 ;
 END
 PORT
  LAYER metal4 ;
  RECT 120.680 763.280 124.220 764.400 ;
  LAYER metal3 ;
  RECT 120.680 763.280 124.220 764.400 ;
  LAYER metal2 ;
  RECT 120.680 763.280 124.220 764.400 ;
  LAYER metal1 ;
  RECT 120.680 763.280 124.220 764.400 ;
 END
 PORT
  LAYER metal4 ;
  RECT 112.000 763.280 115.540 764.400 ;
  LAYER metal3 ;
  RECT 112.000 763.280 115.540 764.400 ;
  LAYER metal2 ;
  RECT 112.000 763.280 115.540 764.400 ;
  LAYER metal1 ;
  RECT 112.000 763.280 115.540 764.400 ;
 END
 PORT
  LAYER metal4 ;
  RECT 103.320 763.280 106.860 764.400 ;
  LAYER metal3 ;
  RECT 103.320 763.280 106.860 764.400 ;
  LAYER metal2 ;
  RECT 103.320 763.280 106.860 764.400 ;
  LAYER metal1 ;
  RECT 103.320 763.280 106.860 764.400 ;
 END
 PORT
  LAYER metal4 ;
  RECT 94.640 763.280 98.180 764.400 ;
  LAYER metal3 ;
  RECT 94.640 763.280 98.180 764.400 ;
  LAYER metal2 ;
  RECT 94.640 763.280 98.180 764.400 ;
  LAYER metal1 ;
  RECT 94.640 763.280 98.180 764.400 ;
 END
 PORT
  LAYER metal4 ;
  RECT 51.240 763.280 54.780 764.400 ;
  LAYER metal3 ;
  RECT 51.240 763.280 54.780 764.400 ;
  LAYER metal2 ;
  RECT 51.240 763.280 54.780 764.400 ;
  LAYER metal1 ;
  RECT 51.240 763.280 54.780 764.400 ;
 END
 PORT
  LAYER metal4 ;
  RECT 42.560 763.280 46.100 764.400 ;
  LAYER metal3 ;
  RECT 42.560 763.280 46.100 764.400 ;
  LAYER metal2 ;
  RECT 42.560 763.280 46.100 764.400 ;
  LAYER metal1 ;
  RECT 42.560 763.280 46.100 764.400 ;
 END
 PORT
  LAYER metal4 ;
  RECT 33.880 763.280 37.420 764.400 ;
  LAYER metal3 ;
  RECT 33.880 763.280 37.420 764.400 ;
  LAYER metal2 ;
  RECT 33.880 763.280 37.420 764.400 ;
  LAYER metal1 ;
  RECT 33.880 763.280 37.420 764.400 ;
 END
 PORT
  LAYER metal4 ;
  RECT 25.200 763.280 28.740 764.400 ;
  LAYER metal3 ;
  RECT 25.200 763.280 28.740 764.400 ;
  LAYER metal2 ;
  RECT 25.200 763.280 28.740 764.400 ;
  LAYER metal1 ;
  RECT 25.200 763.280 28.740 764.400 ;
 END
 PORT
  LAYER metal4 ;
  RECT 16.520 763.280 20.060 764.400 ;
  LAYER metal3 ;
  RECT 16.520 763.280 20.060 764.400 ;
  LAYER metal2 ;
  RECT 16.520 763.280 20.060 764.400 ;
  LAYER metal1 ;
  RECT 16.520 763.280 20.060 764.400 ;
 END
 PORT
  LAYER metal4 ;
  RECT 7.840 763.280 11.380 764.400 ;
  LAYER metal3 ;
  RECT 7.840 763.280 11.380 764.400 ;
  LAYER metal2 ;
  RECT 7.840 763.280 11.380 764.400 ;
  LAYER metal1 ;
  RECT 7.840 763.280 11.380 764.400 ;
 END
 PORT
  LAYER metal4 ;
  RECT 325.900 0.000 329.440 1.120 ;
  LAYER metal3 ;
  RECT 325.900 0.000 329.440 1.120 ;
  LAYER metal2 ;
  RECT 325.900 0.000 329.440 1.120 ;
  LAYER metal1 ;
  RECT 325.900 0.000 329.440 1.120 ;
 END
 PORT
  LAYER metal4 ;
  RECT 304.200 0.000 307.740 1.120 ;
  LAYER metal3 ;
  RECT 304.200 0.000 307.740 1.120 ;
  LAYER metal2 ;
  RECT 304.200 0.000 307.740 1.120 ;
  LAYER metal1 ;
  RECT 304.200 0.000 307.740 1.120 ;
 END
 PORT
  LAYER metal4 ;
  RECT 287.460 0.000 291.000 1.120 ;
  LAYER metal3 ;
  RECT 287.460 0.000 291.000 1.120 ;
  LAYER metal2 ;
  RECT 287.460 0.000 291.000 1.120 ;
  LAYER metal1 ;
  RECT 287.460 0.000 291.000 1.120 ;
 END
 PORT
  LAYER metal4 ;
  RECT 261.420 0.000 264.960 1.120 ;
  LAYER metal3 ;
  RECT 261.420 0.000 264.960 1.120 ;
  LAYER metal2 ;
  RECT 261.420 0.000 264.960 1.120 ;
  LAYER metal1 ;
  RECT 261.420 0.000 264.960 1.120 ;
 END
 PORT
  LAYER metal4 ;
  RECT 239.720 0.000 243.260 1.120 ;
  LAYER metal3 ;
  RECT 239.720 0.000 243.260 1.120 ;
  LAYER metal2 ;
  RECT 239.720 0.000 243.260 1.120 ;
  LAYER metal1 ;
  RECT 239.720 0.000 243.260 1.120 ;
 END
 PORT
  LAYER metal4 ;
  RECT 218.020 0.000 221.560 1.120 ;
  LAYER metal3 ;
  RECT 218.020 0.000 221.560 1.120 ;
  LAYER metal2 ;
  RECT 218.020 0.000 221.560 1.120 ;
  LAYER metal1 ;
  RECT 218.020 0.000 221.560 1.120 ;
 END
 PORT
  LAYER metal4 ;
  RECT 121.920 0.000 125.460 1.120 ;
  LAYER metal3 ;
  RECT 121.920 0.000 125.460 1.120 ;
  LAYER metal2 ;
  RECT 121.920 0.000 125.460 1.120 ;
  LAYER metal1 ;
  RECT 121.920 0.000 125.460 1.120 ;
 END
 PORT
  LAYER metal4 ;
  RECT 100.220 0.000 103.760 1.120 ;
  LAYER metal3 ;
  RECT 100.220 0.000 103.760 1.120 ;
  LAYER metal2 ;
  RECT 100.220 0.000 103.760 1.120 ;
  LAYER metal1 ;
  RECT 100.220 0.000 103.760 1.120 ;
 END
 PORT
  LAYER metal4 ;
  RECT 83.480 0.000 87.020 1.120 ;
  LAYER metal3 ;
  RECT 83.480 0.000 87.020 1.120 ;
  LAYER metal2 ;
  RECT 83.480 0.000 87.020 1.120 ;
  LAYER metal1 ;
  RECT 83.480 0.000 87.020 1.120 ;
 END
 PORT
  LAYER metal4 ;
  RECT 56.820 0.000 60.360 1.120 ;
  LAYER metal3 ;
  RECT 56.820 0.000 60.360 1.120 ;
  LAYER metal2 ;
  RECT 56.820 0.000 60.360 1.120 ;
  LAYER metal1 ;
  RECT 56.820 0.000 60.360 1.120 ;
 END
 PORT
  LAYER metal4 ;
  RECT 35.740 0.000 39.280 1.120 ;
  LAYER metal3 ;
  RECT 35.740 0.000 39.280 1.120 ;
  LAYER metal2 ;
  RECT 35.740 0.000 39.280 1.120 ;
  LAYER metal1 ;
  RECT 35.740 0.000 39.280 1.120 ;
 END
 PORT
  LAYER metal4 ;
  RECT 14.040 0.000 17.580 1.120 ;
  LAYER metal3 ;
  RECT 14.040 0.000 17.580 1.120 ;
  LAYER metal2 ;
  RECT 14.040 0.000 17.580 1.120 ;
  LAYER metal1 ;
  RECT 14.040 0.000 17.580 1.120 ;
 END
END VCC
PIN GND
  DIRECTION INOUT ;
  USE GROUND ;
  SHAPE ABUTMENT ;
 PORT
  LAYER metal4 ;
  RECT 336.160 749.060 337.280 752.300 ;
  LAYER metal3 ;
  RECT 336.160 749.060 337.280 752.300 ;
  LAYER metal2 ;
  RECT 336.160 749.060 337.280 752.300 ;
  LAYER metal1 ;
  RECT 336.160 749.060 337.280 752.300 ;
 END
 PORT
  LAYER metal4 ;
  RECT 336.160 741.220 337.280 744.460 ;
  LAYER metal3 ;
  RECT 336.160 741.220 337.280 744.460 ;
  LAYER metal2 ;
  RECT 336.160 741.220 337.280 744.460 ;
  LAYER metal1 ;
  RECT 336.160 741.220 337.280 744.460 ;
 END
 PORT
  LAYER metal4 ;
  RECT 336.160 733.380 337.280 736.620 ;
  LAYER metal3 ;
  RECT 336.160 733.380 337.280 736.620 ;
  LAYER metal2 ;
  RECT 336.160 733.380 337.280 736.620 ;
  LAYER metal1 ;
  RECT 336.160 733.380 337.280 736.620 ;
 END
 PORT
  LAYER metal4 ;
  RECT 336.160 725.540 337.280 728.780 ;
  LAYER metal3 ;
  RECT 336.160 725.540 337.280 728.780 ;
  LAYER metal2 ;
  RECT 336.160 725.540 337.280 728.780 ;
  LAYER metal1 ;
  RECT 336.160 725.540 337.280 728.780 ;
 END
 PORT
  LAYER metal4 ;
  RECT 336.160 717.700 337.280 720.940 ;
  LAYER metal3 ;
  RECT 336.160 717.700 337.280 720.940 ;
  LAYER metal2 ;
  RECT 336.160 717.700 337.280 720.940 ;
  LAYER metal1 ;
  RECT 336.160 717.700 337.280 720.940 ;
 END
 PORT
  LAYER metal4 ;
  RECT 336.160 678.500 337.280 681.740 ;
  LAYER metal3 ;
  RECT 336.160 678.500 337.280 681.740 ;
  LAYER metal2 ;
  RECT 336.160 678.500 337.280 681.740 ;
  LAYER metal1 ;
  RECT 336.160 678.500 337.280 681.740 ;
 END
 PORT
  LAYER metal4 ;
  RECT 336.160 670.660 337.280 673.900 ;
  LAYER metal3 ;
  RECT 336.160 670.660 337.280 673.900 ;
  LAYER metal2 ;
  RECT 336.160 670.660 337.280 673.900 ;
  LAYER metal1 ;
  RECT 336.160 670.660 337.280 673.900 ;
 END
 PORT
  LAYER metal4 ;
  RECT 336.160 662.820 337.280 666.060 ;
  LAYER metal3 ;
  RECT 336.160 662.820 337.280 666.060 ;
  LAYER metal2 ;
  RECT 336.160 662.820 337.280 666.060 ;
  LAYER metal1 ;
  RECT 336.160 662.820 337.280 666.060 ;
 END
 PORT
  LAYER metal4 ;
  RECT 336.160 654.980 337.280 658.220 ;
  LAYER metal3 ;
  RECT 336.160 654.980 337.280 658.220 ;
  LAYER metal2 ;
  RECT 336.160 654.980 337.280 658.220 ;
  LAYER metal1 ;
  RECT 336.160 654.980 337.280 658.220 ;
 END
 PORT
  LAYER metal4 ;
  RECT 336.160 647.140 337.280 650.380 ;
  LAYER metal3 ;
  RECT 336.160 647.140 337.280 650.380 ;
  LAYER metal2 ;
  RECT 336.160 647.140 337.280 650.380 ;
  LAYER metal1 ;
  RECT 336.160 647.140 337.280 650.380 ;
 END
 PORT
  LAYER metal4 ;
  RECT 336.160 639.300 337.280 642.540 ;
  LAYER metal3 ;
  RECT 336.160 639.300 337.280 642.540 ;
  LAYER metal2 ;
  RECT 336.160 639.300 337.280 642.540 ;
  LAYER metal1 ;
  RECT 336.160 639.300 337.280 642.540 ;
 END
 PORT
  LAYER metal4 ;
  RECT 336.160 600.100 337.280 603.340 ;
  LAYER metal3 ;
  RECT 336.160 600.100 337.280 603.340 ;
  LAYER metal2 ;
  RECT 336.160 600.100 337.280 603.340 ;
  LAYER metal1 ;
  RECT 336.160 600.100 337.280 603.340 ;
 END
 PORT
  LAYER metal4 ;
  RECT 336.160 592.260 337.280 595.500 ;
  LAYER metal3 ;
  RECT 336.160 592.260 337.280 595.500 ;
  LAYER metal2 ;
  RECT 336.160 592.260 337.280 595.500 ;
  LAYER metal1 ;
  RECT 336.160 592.260 337.280 595.500 ;
 END
 PORT
  LAYER metal4 ;
  RECT 336.160 584.420 337.280 587.660 ;
  LAYER metal3 ;
  RECT 336.160 584.420 337.280 587.660 ;
  LAYER metal2 ;
  RECT 336.160 584.420 337.280 587.660 ;
  LAYER metal1 ;
  RECT 336.160 584.420 337.280 587.660 ;
 END
 PORT
  LAYER metal4 ;
  RECT 336.160 576.580 337.280 579.820 ;
  LAYER metal3 ;
  RECT 336.160 576.580 337.280 579.820 ;
  LAYER metal2 ;
  RECT 336.160 576.580 337.280 579.820 ;
  LAYER metal1 ;
  RECT 336.160 576.580 337.280 579.820 ;
 END
 PORT
  LAYER metal4 ;
  RECT 336.160 568.740 337.280 571.980 ;
  LAYER metal3 ;
  RECT 336.160 568.740 337.280 571.980 ;
  LAYER metal2 ;
  RECT 336.160 568.740 337.280 571.980 ;
  LAYER metal1 ;
  RECT 336.160 568.740 337.280 571.980 ;
 END
 PORT
  LAYER metal4 ;
  RECT 336.160 560.900 337.280 564.140 ;
  LAYER metal3 ;
  RECT 336.160 560.900 337.280 564.140 ;
  LAYER metal2 ;
  RECT 336.160 560.900 337.280 564.140 ;
  LAYER metal1 ;
  RECT 336.160 560.900 337.280 564.140 ;
 END
 PORT
  LAYER metal4 ;
  RECT 336.160 521.700 337.280 524.940 ;
  LAYER metal3 ;
  RECT 336.160 521.700 337.280 524.940 ;
  LAYER metal2 ;
  RECT 336.160 521.700 337.280 524.940 ;
  LAYER metal1 ;
  RECT 336.160 521.700 337.280 524.940 ;
 END
 PORT
  LAYER metal4 ;
  RECT 336.160 513.860 337.280 517.100 ;
  LAYER metal3 ;
  RECT 336.160 513.860 337.280 517.100 ;
  LAYER metal2 ;
  RECT 336.160 513.860 337.280 517.100 ;
  LAYER metal1 ;
  RECT 336.160 513.860 337.280 517.100 ;
 END
 PORT
  LAYER metal4 ;
  RECT 336.160 506.020 337.280 509.260 ;
  LAYER metal3 ;
  RECT 336.160 506.020 337.280 509.260 ;
  LAYER metal2 ;
  RECT 336.160 506.020 337.280 509.260 ;
  LAYER metal1 ;
  RECT 336.160 506.020 337.280 509.260 ;
 END
 PORT
  LAYER metal4 ;
  RECT 336.160 498.180 337.280 501.420 ;
  LAYER metal3 ;
  RECT 336.160 498.180 337.280 501.420 ;
  LAYER metal2 ;
  RECT 336.160 498.180 337.280 501.420 ;
  LAYER metal1 ;
  RECT 336.160 498.180 337.280 501.420 ;
 END
 PORT
  LAYER metal4 ;
  RECT 336.160 490.340 337.280 493.580 ;
  LAYER metal3 ;
  RECT 336.160 490.340 337.280 493.580 ;
  LAYER metal2 ;
  RECT 336.160 490.340 337.280 493.580 ;
  LAYER metal1 ;
  RECT 336.160 490.340 337.280 493.580 ;
 END
 PORT
  LAYER metal4 ;
  RECT 336.160 482.500 337.280 485.740 ;
  LAYER metal3 ;
  RECT 336.160 482.500 337.280 485.740 ;
  LAYER metal2 ;
  RECT 336.160 482.500 337.280 485.740 ;
  LAYER metal1 ;
  RECT 336.160 482.500 337.280 485.740 ;
 END
 PORT
  LAYER metal4 ;
  RECT 336.160 443.300 337.280 446.540 ;
  LAYER metal3 ;
  RECT 336.160 443.300 337.280 446.540 ;
  LAYER metal2 ;
  RECT 336.160 443.300 337.280 446.540 ;
  LAYER metal1 ;
  RECT 336.160 443.300 337.280 446.540 ;
 END
 PORT
  LAYER metal4 ;
  RECT 336.160 435.460 337.280 438.700 ;
  LAYER metal3 ;
  RECT 336.160 435.460 337.280 438.700 ;
  LAYER metal2 ;
  RECT 336.160 435.460 337.280 438.700 ;
  LAYER metal1 ;
  RECT 336.160 435.460 337.280 438.700 ;
 END
 PORT
  LAYER metal4 ;
  RECT 336.160 427.620 337.280 430.860 ;
  LAYER metal3 ;
  RECT 336.160 427.620 337.280 430.860 ;
  LAYER metal2 ;
  RECT 336.160 427.620 337.280 430.860 ;
  LAYER metal1 ;
  RECT 336.160 427.620 337.280 430.860 ;
 END
 PORT
  LAYER metal4 ;
  RECT 336.160 419.780 337.280 423.020 ;
  LAYER metal3 ;
  RECT 336.160 419.780 337.280 423.020 ;
  LAYER metal2 ;
  RECT 336.160 419.780 337.280 423.020 ;
  LAYER metal1 ;
  RECT 336.160 419.780 337.280 423.020 ;
 END
 PORT
  LAYER metal4 ;
  RECT 336.160 411.940 337.280 415.180 ;
  LAYER metal3 ;
  RECT 336.160 411.940 337.280 415.180 ;
  LAYER metal2 ;
  RECT 336.160 411.940 337.280 415.180 ;
  LAYER metal1 ;
  RECT 336.160 411.940 337.280 415.180 ;
 END
 PORT
  LAYER metal4 ;
  RECT 336.160 404.100 337.280 407.340 ;
  LAYER metal3 ;
  RECT 336.160 404.100 337.280 407.340 ;
  LAYER metal2 ;
  RECT 336.160 404.100 337.280 407.340 ;
  LAYER metal1 ;
  RECT 336.160 404.100 337.280 407.340 ;
 END
 PORT
  LAYER metal4 ;
  RECT 336.160 364.900 337.280 368.140 ;
  LAYER metal3 ;
  RECT 336.160 364.900 337.280 368.140 ;
  LAYER metal2 ;
  RECT 336.160 364.900 337.280 368.140 ;
  LAYER metal1 ;
  RECT 336.160 364.900 337.280 368.140 ;
 END
 PORT
  LAYER metal4 ;
  RECT 336.160 357.060 337.280 360.300 ;
  LAYER metal3 ;
  RECT 336.160 357.060 337.280 360.300 ;
  LAYER metal2 ;
  RECT 336.160 357.060 337.280 360.300 ;
  LAYER metal1 ;
  RECT 336.160 357.060 337.280 360.300 ;
 END
 PORT
  LAYER metal4 ;
  RECT 336.160 349.220 337.280 352.460 ;
  LAYER metal3 ;
  RECT 336.160 349.220 337.280 352.460 ;
  LAYER metal2 ;
  RECT 336.160 349.220 337.280 352.460 ;
  LAYER metal1 ;
  RECT 336.160 349.220 337.280 352.460 ;
 END
 PORT
  LAYER metal4 ;
  RECT 336.160 341.380 337.280 344.620 ;
  LAYER metal3 ;
  RECT 336.160 341.380 337.280 344.620 ;
  LAYER metal2 ;
  RECT 336.160 341.380 337.280 344.620 ;
  LAYER metal1 ;
  RECT 336.160 341.380 337.280 344.620 ;
 END
 PORT
  LAYER metal4 ;
  RECT 336.160 333.540 337.280 336.780 ;
  LAYER metal3 ;
  RECT 336.160 333.540 337.280 336.780 ;
  LAYER metal2 ;
  RECT 336.160 333.540 337.280 336.780 ;
  LAYER metal1 ;
  RECT 336.160 333.540 337.280 336.780 ;
 END
 PORT
  LAYER metal4 ;
  RECT 336.160 325.700 337.280 328.940 ;
  LAYER metal3 ;
  RECT 336.160 325.700 337.280 328.940 ;
  LAYER metal2 ;
  RECT 336.160 325.700 337.280 328.940 ;
  LAYER metal1 ;
  RECT 336.160 325.700 337.280 328.940 ;
 END
 PORT
  LAYER metal4 ;
  RECT 336.160 286.500 337.280 289.740 ;
  LAYER metal3 ;
  RECT 336.160 286.500 337.280 289.740 ;
  LAYER metal2 ;
  RECT 336.160 286.500 337.280 289.740 ;
  LAYER metal1 ;
  RECT 336.160 286.500 337.280 289.740 ;
 END
 PORT
  LAYER metal4 ;
  RECT 336.160 278.660 337.280 281.900 ;
  LAYER metal3 ;
  RECT 336.160 278.660 337.280 281.900 ;
  LAYER metal2 ;
  RECT 336.160 278.660 337.280 281.900 ;
  LAYER metal1 ;
  RECT 336.160 278.660 337.280 281.900 ;
 END
 PORT
  LAYER metal4 ;
  RECT 336.160 270.820 337.280 274.060 ;
  LAYER metal3 ;
  RECT 336.160 270.820 337.280 274.060 ;
  LAYER metal2 ;
  RECT 336.160 270.820 337.280 274.060 ;
  LAYER metal1 ;
  RECT 336.160 270.820 337.280 274.060 ;
 END
 PORT
  LAYER metal4 ;
  RECT 336.160 262.980 337.280 266.220 ;
  LAYER metal3 ;
  RECT 336.160 262.980 337.280 266.220 ;
  LAYER metal2 ;
  RECT 336.160 262.980 337.280 266.220 ;
  LAYER metal1 ;
  RECT 336.160 262.980 337.280 266.220 ;
 END
 PORT
  LAYER metal4 ;
  RECT 336.160 255.140 337.280 258.380 ;
  LAYER metal3 ;
  RECT 336.160 255.140 337.280 258.380 ;
  LAYER metal2 ;
  RECT 336.160 255.140 337.280 258.380 ;
  LAYER metal1 ;
  RECT 336.160 255.140 337.280 258.380 ;
 END
 PORT
  LAYER metal4 ;
  RECT 336.160 247.300 337.280 250.540 ;
  LAYER metal3 ;
  RECT 336.160 247.300 337.280 250.540 ;
  LAYER metal2 ;
  RECT 336.160 247.300 337.280 250.540 ;
  LAYER metal1 ;
  RECT 336.160 247.300 337.280 250.540 ;
 END
 PORT
  LAYER metal4 ;
  RECT 336.160 208.100 337.280 211.340 ;
  LAYER metal3 ;
  RECT 336.160 208.100 337.280 211.340 ;
  LAYER metal2 ;
  RECT 336.160 208.100 337.280 211.340 ;
  LAYER metal1 ;
  RECT 336.160 208.100 337.280 211.340 ;
 END
 PORT
  LAYER metal4 ;
  RECT 336.160 200.260 337.280 203.500 ;
  LAYER metal3 ;
  RECT 336.160 200.260 337.280 203.500 ;
  LAYER metal2 ;
  RECT 336.160 200.260 337.280 203.500 ;
  LAYER metal1 ;
  RECT 336.160 200.260 337.280 203.500 ;
 END
 PORT
  LAYER metal4 ;
  RECT 336.160 192.420 337.280 195.660 ;
  LAYER metal3 ;
  RECT 336.160 192.420 337.280 195.660 ;
  LAYER metal2 ;
  RECT 336.160 192.420 337.280 195.660 ;
  LAYER metal1 ;
  RECT 336.160 192.420 337.280 195.660 ;
 END
 PORT
  LAYER metal4 ;
  RECT 336.160 184.580 337.280 187.820 ;
  LAYER metal3 ;
  RECT 336.160 184.580 337.280 187.820 ;
  LAYER metal2 ;
  RECT 336.160 184.580 337.280 187.820 ;
  LAYER metal1 ;
  RECT 336.160 184.580 337.280 187.820 ;
 END
 PORT
  LAYER metal4 ;
  RECT 336.160 176.740 337.280 179.980 ;
  LAYER metal3 ;
  RECT 336.160 176.740 337.280 179.980 ;
  LAYER metal2 ;
  RECT 336.160 176.740 337.280 179.980 ;
  LAYER metal1 ;
  RECT 336.160 176.740 337.280 179.980 ;
 END
 PORT
  LAYER metal4 ;
  RECT 336.160 168.900 337.280 172.140 ;
  LAYER metal3 ;
  RECT 336.160 168.900 337.280 172.140 ;
  LAYER metal2 ;
  RECT 336.160 168.900 337.280 172.140 ;
  LAYER metal1 ;
  RECT 336.160 168.900 337.280 172.140 ;
 END
 PORT
  LAYER metal4 ;
  RECT 336.160 129.700 337.280 132.940 ;
  LAYER metal3 ;
  RECT 336.160 129.700 337.280 132.940 ;
  LAYER metal2 ;
  RECT 336.160 129.700 337.280 132.940 ;
  LAYER metal1 ;
  RECT 336.160 129.700 337.280 132.940 ;
 END
 PORT
  LAYER metal4 ;
  RECT 336.160 121.860 337.280 125.100 ;
  LAYER metal3 ;
  RECT 336.160 121.860 337.280 125.100 ;
  LAYER metal2 ;
  RECT 336.160 121.860 337.280 125.100 ;
  LAYER metal1 ;
  RECT 336.160 121.860 337.280 125.100 ;
 END
 PORT
  LAYER metal4 ;
  RECT 336.160 114.020 337.280 117.260 ;
  LAYER metal3 ;
  RECT 336.160 114.020 337.280 117.260 ;
  LAYER metal2 ;
  RECT 336.160 114.020 337.280 117.260 ;
  LAYER metal1 ;
  RECT 336.160 114.020 337.280 117.260 ;
 END
 PORT
  LAYER metal4 ;
  RECT 336.160 106.180 337.280 109.420 ;
  LAYER metal3 ;
  RECT 336.160 106.180 337.280 109.420 ;
  LAYER metal2 ;
  RECT 336.160 106.180 337.280 109.420 ;
  LAYER metal1 ;
  RECT 336.160 106.180 337.280 109.420 ;
 END
 PORT
  LAYER metal4 ;
  RECT 336.160 98.340 337.280 101.580 ;
  LAYER metal3 ;
  RECT 336.160 98.340 337.280 101.580 ;
  LAYER metal2 ;
  RECT 336.160 98.340 337.280 101.580 ;
  LAYER metal1 ;
  RECT 336.160 98.340 337.280 101.580 ;
 END
 PORT
  LAYER metal4 ;
  RECT 336.160 90.500 337.280 93.740 ;
  LAYER metal3 ;
  RECT 336.160 90.500 337.280 93.740 ;
  LAYER metal2 ;
  RECT 336.160 90.500 337.280 93.740 ;
  LAYER metal1 ;
  RECT 336.160 90.500 337.280 93.740 ;
 END
 PORT
  LAYER metal4 ;
  RECT 336.160 51.300 337.280 54.540 ;
  LAYER metal3 ;
  RECT 336.160 51.300 337.280 54.540 ;
  LAYER metal2 ;
  RECT 336.160 51.300 337.280 54.540 ;
  LAYER metal1 ;
  RECT 336.160 51.300 337.280 54.540 ;
 END
 PORT
  LAYER metal4 ;
  RECT 336.160 43.460 337.280 46.700 ;
  LAYER metal3 ;
  RECT 336.160 43.460 337.280 46.700 ;
  LAYER metal2 ;
  RECT 336.160 43.460 337.280 46.700 ;
  LAYER metal1 ;
  RECT 336.160 43.460 337.280 46.700 ;
 END
 PORT
  LAYER metal4 ;
  RECT 336.160 35.620 337.280 38.860 ;
  LAYER metal3 ;
  RECT 336.160 35.620 337.280 38.860 ;
  LAYER metal2 ;
  RECT 336.160 35.620 337.280 38.860 ;
  LAYER metal1 ;
  RECT 336.160 35.620 337.280 38.860 ;
 END
 PORT
  LAYER metal4 ;
  RECT 336.160 27.780 337.280 31.020 ;
  LAYER metal3 ;
  RECT 336.160 27.780 337.280 31.020 ;
  LAYER metal2 ;
  RECT 336.160 27.780 337.280 31.020 ;
  LAYER metal1 ;
  RECT 336.160 27.780 337.280 31.020 ;
 END
 PORT
  LAYER metal4 ;
  RECT 336.160 19.940 337.280 23.180 ;
  LAYER metal3 ;
  RECT 336.160 19.940 337.280 23.180 ;
  LAYER metal2 ;
  RECT 336.160 19.940 337.280 23.180 ;
  LAYER metal1 ;
  RECT 336.160 19.940 337.280 23.180 ;
 END
 PORT
  LAYER metal4 ;
  RECT 336.160 12.100 337.280 15.340 ;
  LAYER metal3 ;
  RECT 336.160 12.100 337.280 15.340 ;
  LAYER metal2 ;
  RECT 336.160 12.100 337.280 15.340 ;
  LAYER metal1 ;
  RECT 336.160 12.100 337.280 15.340 ;
 END
 PORT
  LAYER metal4 ;
  RECT 0.000 749.060 1.120 752.300 ;
  LAYER metal3 ;
  RECT 0.000 749.060 1.120 752.300 ;
  LAYER metal2 ;
  RECT 0.000 749.060 1.120 752.300 ;
  LAYER metal1 ;
  RECT 0.000 749.060 1.120 752.300 ;
 END
 PORT
  LAYER metal4 ;
  RECT 0.000 741.220 1.120 744.460 ;
  LAYER metal3 ;
  RECT 0.000 741.220 1.120 744.460 ;
  LAYER metal2 ;
  RECT 0.000 741.220 1.120 744.460 ;
  LAYER metal1 ;
  RECT 0.000 741.220 1.120 744.460 ;
 END
 PORT
  LAYER metal4 ;
  RECT 0.000 733.380 1.120 736.620 ;
  LAYER metal3 ;
  RECT 0.000 733.380 1.120 736.620 ;
  LAYER metal2 ;
  RECT 0.000 733.380 1.120 736.620 ;
  LAYER metal1 ;
  RECT 0.000 733.380 1.120 736.620 ;
 END
 PORT
  LAYER metal4 ;
  RECT 0.000 725.540 1.120 728.780 ;
  LAYER metal3 ;
  RECT 0.000 725.540 1.120 728.780 ;
  LAYER metal2 ;
  RECT 0.000 725.540 1.120 728.780 ;
  LAYER metal1 ;
  RECT 0.000 725.540 1.120 728.780 ;
 END
 PORT
  LAYER metal4 ;
  RECT 0.000 717.700 1.120 720.940 ;
  LAYER metal3 ;
  RECT 0.000 717.700 1.120 720.940 ;
  LAYER metal2 ;
  RECT 0.000 717.700 1.120 720.940 ;
  LAYER metal1 ;
  RECT 0.000 717.700 1.120 720.940 ;
 END
 PORT
  LAYER metal4 ;
  RECT 0.000 678.500 1.120 681.740 ;
  LAYER metal3 ;
  RECT 0.000 678.500 1.120 681.740 ;
  LAYER metal2 ;
  RECT 0.000 678.500 1.120 681.740 ;
  LAYER metal1 ;
  RECT 0.000 678.500 1.120 681.740 ;
 END
 PORT
  LAYER metal4 ;
  RECT 0.000 670.660 1.120 673.900 ;
  LAYER metal3 ;
  RECT 0.000 670.660 1.120 673.900 ;
  LAYER metal2 ;
  RECT 0.000 670.660 1.120 673.900 ;
  LAYER metal1 ;
  RECT 0.000 670.660 1.120 673.900 ;
 END
 PORT
  LAYER metal4 ;
  RECT 0.000 662.820 1.120 666.060 ;
  LAYER metal3 ;
  RECT 0.000 662.820 1.120 666.060 ;
  LAYER metal2 ;
  RECT 0.000 662.820 1.120 666.060 ;
  LAYER metal1 ;
  RECT 0.000 662.820 1.120 666.060 ;
 END
 PORT
  LAYER metal4 ;
  RECT 0.000 654.980 1.120 658.220 ;
  LAYER metal3 ;
  RECT 0.000 654.980 1.120 658.220 ;
  LAYER metal2 ;
  RECT 0.000 654.980 1.120 658.220 ;
  LAYER metal1 ;
  RECT 0.000 654.980 1.120 658.220 ;
 END
 PORT
  LAYER metal4 ;
  RECT 0.000 647.140 1.120 650.380 ;
  LAYER metal3 ;
  RECT 0.000 647.140 1.120 650.380 ;
  LAYER metal2 ;
  RECT 0.000 647.140 1.120 650.380 ;
  LAYER metal1 ;
  RECT 0.000 647.140 1.120 650.380 ;
 END
 PORT
  LAYER metal4 ;
  RECT 0.000 639.300 1.120 642.540 ;
  LAYER metal3 ;
  RECT 0.000 639.300 1.120 642.540 ;
  LAYER metal2 ;
  RECT 0.000 639.300 1.120 642.540 ;
  LAYER metal1 ;
  RECT 0.000 639.300 1.120 642.540 ;
 END
 PORT
  LAYER metal4 ;
  RECT 0.000 600.100 1.120 603.340 ;
  LAYER metal3 ;
  RECT 0.000 600.100 1.120 603.340 ;
  LAYER metal2 ;
  RECT 0.000 600.100 1.120 603.340 ;
  LAYER metal1 ;
  RECT 0.000 600.100 1.120 603.340 ;
 END
 PORT
  LAYER metal4 ;
  RECT 0.000 592.260 1.120 595.500 ;
  LAYER metal3 ;
  RECT 0.000 592.260 1.120 595.500 ;
  LAYER metal2 ;
  RECT 0.000 592.260 1.120 595.500 ;
  LAYER metal1 ;
  RECT 0.000 592.260 1.120 595.500 ;
 END
 PORT
  LAYER metal4 ;
  RECT 0.000 584.420 1.120 587.660 ;
  LAYER metal3 ;
  RECT 0.000 584.420 1.120 587.660 ;
  LAYER metal2 ;
  RECT 0.000 584.420 1.120 587.660 ;
  LAYER metal1 ;
  RECT 0.000 584.420 1.120 587.660 ;
 END
 PORT
  LAYER metal4 ;
  RECT 0.000 576.580 1.120 579.820 ;
  LAYER metal3 ;
  RECT 0.000 576.580 1.120 579.820 ;
  LAYER metal2 ;
  RECT 0.000 576.580 1.120 579.820 ;
  LAYER metal1 ;
  RECT 0.000 576.580 1.120 579.820 ;
 END
 PORT
  LAYER metal4 ;
  RECT 0.000 568.740 1.120 571.980 ;
  LAYER metal3 ;
  RECT 0.000 568.740 1.120 571.980 ;
  LAYER metal2 ;
  RECT 0.000 568.740 1.120 571.980 ;
  LAYER metal1 ;
  RECT 0.000 568.740 1.120 571.980 ;
 END
 PORT
  LAYER metal4 ;
  RECT 0.000 560.900 1.120 564.140 ;
  LAYER metal3 ;
  RECT 0.000 560.900 1.120 564.140 ;
  LAYER metal2 ;
  RECT 0.000 560.900 1.120 564.140 ;
  LAYER metal1 ;
  RECT 0.000 560.900 1.120 564.140 ;
 END
 PORT
  LAYER metal4 ;
  RECT 0.000 521.700 1.120 524.940 ;
  LAYER metal3 ;
  RECT 0.000 521.700 1.120 524.940 ;
  LAYER metal2 ;
  RECT 0.000 521.700 1.120 524.940 ;
  LAYER metal1 ;
  RECT 0.000 521.700 1.120 524.940 ;
 END
 PORT
  LAYER metal4 ;
  RECT 0.000 513.860 1.120 517.100 ;
  LAYER metal3 ;
  RECT 0.000 513.860 1.120 517.100 ;
  LAYER metal2 ;
  RECT 0.000 513.860 1.120 517.100 ;
  LAYER metal1 ;
  RECT 0.000 513.860 1.120 517.100 ;
 END
 PORT
  LAYER metal4 ;
  RECT 0.000 506.020 1.120 509.260 ;
  LAYER metal3 ;
  RECT 0.000 506.020 1.120 509.260 ;
  LAYER metal2 ;
  RECT 0.000 506.020 1.120 509.260 ;
  LAYER metal1 ;
  RECT 0.000 506.020 1.120 509.260 ;
 END
 PORT
  LAYER metal4 ;
  RECT 0.000 498.180 1.120 501.420 ;
  LAYER metal3 ;
  RECT 0.000 498.180 1.120 501.420 ;
  LAYER metal2 ;
  RECT 0.000 498.180 1.120 501.420 ;
  LAYER metal1 ;
  RECT 0.000 498.180 1.120 501.420 ;
 END
 PORT
  LAYER metal4 ;
  RECT 0.000 490.340 1.120 493.580 ;
  LAYER metal3 ;
  RECT 0.000 490.340 1.120 493.580 ;
  LAYER metal2 ;
  RECT 0.000 490.340 1.120 493.580 ;
  LAYER metal1 ;
  RECT 0.000 490.340 1.120 493.580 ;
 END
 PORT
  LAYER metal4 ;
  RECT 0.000 482.500 1.120 485.740 ;
  LAYER metal3 ;
  RECT 0.000 482.500 1.120 485.740 ;
  LAYER metal2 ;
  RECT 0.000 482.500 1.120 485.740 ;
  LAYER metal1 ;
  RECT 0.000 482.500 1.120 485.740 ;
 END
 PORT
  LAYER metal4 ;
  RECT 0.000 443.300 1.120 446.540 ;
  LAYER metal3 ;
  RECT 0.000 443.300 1.120 446.540 ;
  LAYER metal2 ;
  RECT 0.000 443.300 1.120 446.540 ;
  LAYER metal1 ;
  RECT 0.000 443.300 1.120 446.540 ;
 END
 PORT
  LAYER metal4 ;
  RECT 0.000 435.460 1.120 438.700 ;
  LAYER metal3 ;
  RECT 0.000 435.460 1.120 438.700 ;
  LAYER metal2 ;
  RECT 0.000 435.460 1.120 438.700 ;
  LAYER metal1 ;
  RECT 0.000 435.460 1.120 438.700 ;
 END
 PORT
  LAYER metal4 ;
  RECT 0.000 427.620 1.120 430.860 ;
  LAYER metal3 ;
  RECT 0.000 427.620 1.120 430.860 ;
  LAYER metal2 ;
  RECT 0.000 427.620 1.120 430.860 ;
  LAYER metal1 ;
  RECT 0.000 427.620 1.120 430.860 ;
 END
 PORT
  LAYER metal4 ;
  RECT 0.000 419.780 1.120 423.020 ;
  LAYER metal3 ;
  RECT 0.000 419.780 1.120 423.020 ;
  LAYER metal2 ;
  RECT 0.000 419.780 1.120 423.020 ;
  LAYER metal1 ;
  RECT 0.000 419.780 1.120 423.020 ;
 END
 PORT
  LAYER metal4 ;
  RECT 0.000 411.940 1.120 415.180 ;
  LAYER metal3 ;
  RECT 0.000 411.940 1.120 415.180 ;
  LAYER metal2 ;
  RECT 0.000 411.940 1.120 415.180 ;
  LAYER metal1 ;
  RECT 0.000 411.940 1.120 415.180 ;
 END
 PORT
  LAYER metal4 ;
  RECT 0.000 404.100 1.120 407.340 ;
  LAYER metal3 ;
  RECT 0.000 404.100 1.120 407.340 ;
  LAYER metal2 ;
  RECT 0.000 404.100 1.120 407.340 ;
  LAYER metal1 ;
  RECT 0.000 404.100 1.120 407.340 ;
 END
 PORT
  LAYER metal4 ;
  RECT 0.000 364.900 1.120 368.140 ;
  LAYER metal3 ;
  RECT 0.000 364.900 1.120 368.140 ;
  LAYER metal2 ;
  RECT 0.000 364.900 1.120 368.140 ;
  LAYER metal1 ;
  RECT 0.000 364.900 1.120 368.140 ;
 END
 PORT
  LAYER metal4 ;
  RECT 0.000 357.060 1.120 360.300 ;
  LAYER metal3 ;
  RECT 0.000 357.060 1.120 360.300 ;
  LAYER metal2 ;
  RECT 0.000 357.060 1.120 360.300 ;
  LAYER metal1 ;
  RECT 0.000 357.060 1.120 360.300 ;
 END
 PORT
  LAYER metal4 ;
  RECT 0.000 349.220 1.120 352.460 ;
  LAYER metal3 ;
  RECT 0.000 349.220 1.120 352.460 ;
  LAYER metal2 ;
  RECT 0.000 349.220 1.120 352.460 ;
  LAYER metal1 ;
  RECT 0.000 349.220 1.120 352.460 ;
 END
 PORT
  LAYER metal4 ;
  RECT 0.000 341.380 1.120 344.620 ;
  LAYER metal3 ;
  RECT 0.000 341.380 1.120 344.620 ;
  LAYER metal2 ;
  RECT 0.000 341.380 1.120 344.620 ;
  LAYER metal1 ;
  RECT 0.000 341.380 1.120 344.620 ;
 END
 PORT
  LAYER metal4 ;
  RECT 0.000 333.540 1.120 336.780 ;
  LAYER metal3 ;
  RECT 0.000 333.540 1.120 336.780 ;
  LAYER metal2 ;
  RECT 0.000 333.540 1.120 336.780 ;
  LAYER metal1 ;
  RECT 0.000 333.540 1.120 336.780 ;
 END
 PORT
  LAYER metal4 ;
  RECT 0.000 325.700 1.120 328.940 ;
  LAYER metal3 ;
  RECT 0.000 325.700 1.120 328.940 ;
  LAYER metal2 ;
  RECT 0.000 325.700 1.120 328.940 ;
  LAYER metal1 ;
  RECT 0.000 325.700 1.120 328.940 ;
 END
 PORT
  LAYER metal4 ;
  RECT 0.000 286.500 1.120 289.740 ;
  LAYER metal3 ;
  RECT 0.000 286.500 1.120 289.740 ;
  LAYER metal2 ;
  RECT 0.000 286.500 1.120 289.740 ;
  LAYER metal1 ;
  RECT 0.000 286.500 1.120 289.740 ;
 END
 PORT
  LAYER metal4 ;
  RECT 0.000 278.660 1.120 281.900 ;
  LAYER metal3 ;
  RECT 0.000 278.660 1.120 281.900 ;
  LAYER metal2 ;
  RECT 0.000 278.660 1.120 281.900 ;
  LAYER metal1 ;
  RECT 0.000 278.660 1.120 281.900 ;
 END
 PORT
  LAYER metal4 ;
  RECT 0.000 270.820 1.120 274.060 ;
  LAYER metal3 ;
  RECT 0.000 270.820 1.120 274.060 ;
  LAYER metal2 ;
  RECT 0.000 270.820 1.120 274.060 ;
  LAYER metal1 ;
  RECT 0.000 270.820 1.120 274.060 ;
 END
 PORT
  LAYER metal4 ;
  RECT 0.000 262.980 1.120 266.220 ;
  LAYER metal3 ;
  RECT 0.000 262.980 1.120 266.220 ;
  LAYER metal2 ;
  RECT 0.000 262.980 1.120 266.220 ;
  LAYER metal1 ;
  RECT 0.000 262.980 1.120 266.220 ;
 END
 PORT
  LAYER metal4 ;
  RECT 0.000 255.140 1.120 258.380 ;
  LAYER metal3 ;
  RECT 0.000 255.140 1.120 258.380 ;
  LAYER metal2 ;
  RECT 0.000 255.140 1.120 258.380 ;
  LAYER metal1 ;
  RECT 0.000 255.140 1.120 258.380 ;
 END
 PORT
  LAYER metal4 ;
  RECT 0.000 247.300 1.120 250.540 ;
  LAYER metal3 ;
  RECT 0.000 247.300 1.120 250.540 ;
  LAYER metal2 ;
  RECT 0.000 247.300 1.120 250.540 ;
  LAYER metal1 ;
  RECT 0.000 247.300 1.120 250.540 ;
 END
 PORT
  LAYER metal4 ;
  RECT 0.000 208.100 1.120 211.340 ;
  LAYER metal3 ;
  RECT 0.000 208.100 1.120 211.340 ;
  LAYER metal2 ;
  RECT 0.000 208.100 1.120 211.340 ;
  LAYER metal1 ;
  RECT 0.000 208.100 1.120 211.340 ;
 END
 PORT
  LAYER metal4 ;
  RECT 0.000 200.260 1.120 203.500 ;
  LAYER metal3 ;
  RECT 0.000 200.260 1.120 203.500 ;
  LAYER metal2 ;
  RECT 0.000 200.260 1.120 203.500 ;
  LAYER metal1 ;
  RECT 0.000 200.260 1.120 203.500 ;
 END
 PORT
  LAYER metal4 ;
  RECT 0.000 192.420 1.120 195.660 ;
  LAYER metal3 ;
  RECT 0.000 192.420 1.120 195.660 ;
  LAYER metal2 ;
  RECT 0.000 192.420 1.120 195.660 ;
  LAYER metal1 ;
  RECT 0.000 192.420 1.120 195.660 ;
 END
 PORT
  LAYER metal4 ;
  RECT 0.000 184.580 1.120 187.820 ;
  LAYER metal3 ;
  RECT 0.000 184.580 1.120 187.820 ;
  LAYER metal2 ;
  RECT 0.000 184.580 1.120 187.820 ;
  LAYER metal1 ;
  RECT 0.000 184.580 1.120 187.820 ;
 END
 PORT
  LAYER metal4 ;
  RECT 0.000 176.740 1.120 179.980 ;
  LAYER metal3 ;
  RECT 0.000 176.740 1.120 179.980 ;
  LAYER metal2 ;
  RECT 0.000 176.740 1.120 179.980 ;
  LAYER metal1 ;
  RECT 0.000 176.740 1.120 179.980 ;
 END
 PORT
  LAYER metal4 ;
  RECT 0.000 168.900 1.120 172.140 ;
  LAYER metal3 ;
  RECT 0.000 168.900 1.120 172.140 ;
  LAYER metal2 ;
  RECT 0.000 168.900 1.120 172.140 ;
  LAYER metal1 ;
  RECT 0.000 168.900 1.120 172.140 ;
 END
 PORT
  LAYER metal4 ;
  RECT 0.000 129.700 1.120 132.940 ;
  LAYER metal3 ;
  RECT 0.000 129.700 1.120 132.940 ;
  LAYER metal2 ;
  RECT 0.000 129.700 1.120 132.940 ;
  LAYER metal1 ;
  RECT 0.000 129.700 1.120 132.940 ;
 END
 PORT
  LAYER metal4 ;
  RECT 0.000 121.860 1.120 125.100 ;
  LAYER metal3 ;
  RECT 0.000 121.860 1.120 125.100 ;
  LAYER metal2 ;
  RECT 0.000 121.860 1.120 125.100 ;
  LAYER metal1 ;
  RECT 0.000 121.860 1.120 125.100 ;
 END
 PORT
  LAYER metal4 ;
  RECT 0.000 114.020 1.120 117.260 ;
  LAYER metal3 ;
  RECT 0.000 114.020 1.120 117.260 ;
  LAYER metal2 ;
  RECT 0.000 114.020 1.120 117.260 ;
  LAYER metal1 ;
  RECT 0.000 114.020 1.120 117.260 ;
 END
 PORT
  LAYER metal4 ;
  RECT 0.000 106.180 1.120 109.420 ;
  LAYER metal3 ;
  RECT 0.000 106.180 1.120 109.420 ;
  LAYER metal2 ;
  RECT 0.000 106.180 1.120 109.420 ;
  LAYER metal1 ;
  RECT 0.000 106.180 1.120 109.420 ;
 END
 PORT
  LAYER metal4 ;
  RECT 0.000 98.340 1.120 101.580 ;
  LAYER metal3 ;
  RECT 0.000 98.340 1.120 101.580 ;
  LAYER metal2 ;
  RECT 0.000 98.340 1.120 101.580 ;
  LAYER metal1 ;
  RECT 0.000 98.340 1.120 101.580 ;
 END
 PORT
  LAYER metal4 ;
  RECT 0.000 90.500 1.120 93.740 ;
  LAYER metal3 ;
  RECT 0.000 90.500 1.120 93.740 ;
  LAYER metal2 ;
  RECT 0.000 90.500 1.120 93.740 ;
  LAYER metal1 ;
  RECT 0.000 90.500 1.120 93.740 ;
 END
 PORT
  LAYER metal4 ;
  RECT 0.000 51.300 1.120 54.540 ;
  LAYER metal3 ;
  RECT 0.000 51.300 1.120 54.540 ;
  LAYER metal2 ;
  RECT 0.000 51.300 1.120 54.540 ;
  LAYER metal1 ;
  RECT 0.000 51.300 1.120 54.540 ;
 END
 PORT
  LAYER metal4 ;
  RECT 0.000 43.460 1.120 46.700 ;
  LAYER metal3 ;
  RECT 0.000 43.460 1.120 46.700 ;
  LAYER metal2 ;
  RECT 0.000 43.460 1.120 46.700 ;
  LAYER metal1 ;
  RECT 0.000 43.460 1.120 46.700 ;
 END
 PORT
  LAYER metal4 ;
  RECT 0.000 35.620 1.120 38.860 ;
  LAYER metal3 ;
  RECT 0.000 35.620 1.120 38.860 ;
  LAYER metal2 ;
  RECT 0.000 35.620 1.120 38.860 ;
  LAYER metal1 ;
  RECT 0.000 35.620 1.120 38.860 ;
 END
 PORT
  LAYER metal4 ;
  RECT 0.000 27.780 1.120 31.020 ;
  LAYER metal3 ;
  RECT 0.000 27.780 1.120 31.020 ;
  LAYER metal2 ;
  RECT 0.000 27.780 1.120 31.020 ;
  LAYER metal1 ;
  RECT 0.000 27.780 1.120 31.020 ;
 END
 PORT
  LAYER metal4 ;
  RECT 0.000 19.940 1.120 23.180 ;
  LAYER metal3 ;
  RECT 0.000 19.940 1.120 23.180 ;
  LAYER metal2 ;
  RECT 0.000 19.940 1.120 23.180 ;
  LAYER metal1 ;
  RECT 0.000 19.940 1.120 23.180 ;
 END
 PORT
  LAYER metal4 ;
  RECT 0.000 12.100 1.120 15.340 ;
  LAYER metal3 ;
  RECT 0.000 12.100 1.120 15.340 ;
  LAYER metal2 ;
  RECT 0.000 12.100 1.120 15.340 ;
  LAYER metal1 ;
  RECT 0.000 12.100 1.120 15.340 ;
 END
 PORT
  LAYER metal4 ;
  RECT 315.980 763.280 319.520 764.400 ;
  LAYER metal3 ;
  RECT 315.980 763.280 319.520 764.400 ;
  LAYER metal2 ;
  RECT 315.980 763.280 319.520 764.400 ;
  LAYER metal1 ;
  RECT 315.980 763.280 319.520 764.400 ;
 END
 PORT
  LAYER metal4 ;
  RECT 307.300 763.280 310.840 764.400 ;
  LAYER metal3 ;
  RECT 307.300 763.280 310.840 764.400 ;
  LAYER metal2 ;
  RECT 307.300 763.280 310.840 764.400 ;
  LAYER metal1 ;
  RECT 307.300 763.280 310.840 764.400 ;
 END
 PORT
  LAYER metal4 ;
  RECT 298.620 763.280 302.160 764.400 ;
  LAYER metal3 ;
  RECT 298.620 763.280 302.160 764.400 ;
  LAYER metal2 ;
  RECT 298.620 763.280 302.160 764.400 ;
  LAYER metal1 ;
  RECT 298.620 763.280 302.160 764.400 ;
 END
 PORT
  LAYER metal4 ;
  RECT 289.940 763.280 293.480 764.400 ;
  LAYER metal3 ;
  RECT 289.940 763.280 293.480 764.400 ;
  LAYER metal2 ;
  RECT 289.940 763.280 293.480 764.400 ;
  LAYER metal1 ;
  RECT 289.940 763.280 293.480 764.400 ;
 END
 PORT
  LAYER metal4 ;
  RECT 281.260 763.280 284.800 764.400 ;
  LAYER metal3 ;
  RECT 281.260 763.280 284.800 764.400 ;
  LAYER metal2 ;
  RECT 281.260 763.280 284.800 764.400 ;
  LAYER metal1 ;
  RECT 281.260 763.280 284.800 764.400 ;
 END
 PORT
  LAYER metal4 ;
  RECT 272.580 763.280 276.120 764.400 ;
  LAYER metal3 ;
  RECT 272.580 763.280 276.120 764.400 ;
  LAYER metal2 ;
  RECT 272.580 763.280 276.120 764.400 ;
  LAYER metal1 ;
  RECT 272.580 763.280 276.120 764.400 ;
 END
 PORT
  LAYER metal4 ;
  RECT 229.180 763.280 232.720 764.400 ;
  LAYER metal3 ;
  RECT 229.180 763.280 232.720 764.400 ;
  LAYER metal2 ;
  RECT 229.180 763.280 232.720 764.400 ;
  LAYER metal1 ;
  RECT 229.180 763.280 232.720 764.400 ;
 END
 PORT
  LAYER metal4 ;
  RECT 220.500 763.280 224.040 764.400 ;
  LAYER metal3 ;
  RECT 220.500 763.280 224.040 764.400 ;
  LAYER metal2 ;
  RECT 220.500 763.280 224.040 764.400 ;
  LAYER metal1 ;
  RECT 220.500 763.280 224.040 764.400 ;
 END
 PORT
  LAYER metal4 ;
  RECT 211.820 763.280 215.360 764.400 ;
  LAYER metal3 ;
  RECT 211.820 763.280 215.360 764.400 ;
  LAYER metal2 ;
  RECT 211.820 763.280 215.360 764.400 ;
  LAYER metal1 ;
  RECT 211.820 763.280 215.360 764.400 ;
 END
 PORT
  LAYER metal4 ;
  RECT 203.140 763.280 206.680 764.400 ;
  LAYER metal3 ;
  RECT 203.140 763.280 206.680 764.400 ;
  LAYER metal2 ;
  RECT 203.140 763.280 206.680 764.400 ;
  LAYER metal1 ;
  RECT 203.140 763.280 206.680 764.400 ;
 END
 PORT
  LAYER metal4 ;
  RECT 194.460 763.280 198.000 764.400 ;
  LAYER metal3 ;
  RECT 194.460 763.280 198.000 764.400 ;
  LAYER metal2 ;
  RECT 194.460 763.280 198.000 764.400 ;
  LAYER metal1 ;
  RECT 194.460 763.280 198.000 764.400 ;
 END
 PORT
  LAYER metal4 ;
  RECT 185.780 763.280 189.320 764.400 ;
  LAYER metal3 ;
  RECT 185.780 763.280 189.320 764.400 ;
  LAYER metal2 ;
  RECT 185.780 763.280 189.320 764.400 ;
  LAYER metal1 ;
  RECT 185.780 763.280 189.320 764.400 ;
 END
 PORT
  LAYER metal4 ;
  RECT 142.380 763.280 145.920 764.400 ;
  LAYER metal3 ;
  RECT 142.380 763.280 145.920 764.400 ;
  LAYER metal2 ;
  RECT 142.380 763.280 145.920 764.400 ;
  LAYER metal1 ;
  RECT 142.380 763.280 145.920 764.400 ;
 END
 PORT
  LAYER metal4 ;
  RECT 133.700 763.280 137.240 764.400 ;
  LAYER metal3 ;
  RECT 133.700 763.280 137.240 764.400 ;
  LAYER metal2 ;
  RECT 133.700 763.280 137.240 764.400 ;
  LAYER metal1 ;
  RECT 133.700 763.280 137.240 764.400 ;
 END
 PORT
  LAYER metal4 ;
  RECT 125.020 763.280 128.560 764.400 ;
  LAYER metal3 ;
  RECT 125.020 763.280 128.560 764.400 ;
  LAYER metal2 ;
  RECT 125.020 763.280 128.560 764.400 ;
  LAYER metal1 ;
  RECT 125.020 763.280 128.560 764.400 ;
 END
 PORT
  LAYER metal4 ;
  RECT 116.340 763.280 119.880 764.400 ;
  LAYER metal3 ;
  RECT 116.340 763.280 119.880 764.400 ;
  LAYER metal2 ;
  RECT 116.340 763.280 119.880 764.400 ;
  LAYER metal1 ;
  RECT 116.340 763.280 119.880 764.400 ;
 END
 PORT
  LAYER metal4 ;
  RECT 107.660 763.280 111.200 764.400 ;
  LAYER metal3 ;
  RECT 107.660 763.280 111.200 764.400 ;
  LAYER metal2 ;
  RECT 107.660 763.280 111.200 764.400 ;
  LAYER metal1 ;
  RECT 107.660 763.280 111.200 764.400 ;
 END
 PORT
  LAYER metal4 ;
  RECT 98.980 763.280 102.520 764.400 ;
  LAYER metal3 ;
  RECT 98.980 763.280 102.520 764.400 ;
  LAYER metal2 ;
  RECT 98.980 763.280 102.520 764.400 ;
  LAYER metal1 ;
  RECT 98.980 763.280 102.520 764.400 ;
 END
 PORT
  LAYER metal4 ;
  RECT 55.580 763.280 59.120 764.400 ;
  LAYER metal3 ;
  RECT 55.580 763.280 59.120 764.400 ;
  LAYER metal2 ;
  RECT 55.580 763.280 59.120 764.400 ;
  LAYER metal1 ;
  RECT 55.580 763.280 59.120 764.400 ;
 END
 PORT
  LAYER metal4 ;
  RECT 46.900 763.280 50.440 764.400 ;
  LAYER metal3 ;
  RECT 46.900 763.280 50.440 764.400 ;
  LAYER metal2 ;
  RECT 46.900 763.280 50.440 764.400 ;
  LAYER metal1 ;
  RECT 46.900 763.280 50.440 764.400 ;
 END
 PORT
  LAYER metal4 ;
  RECT 38.220 763.280 41.760 764.400 ;
  LAYER metal3 ;
  RECT 38.220 763.280 41.760 764.400 ;
  LAYER metal2 ;
  RECT 38.220 763.280 41.760 764.400 ;
  LAYER metal1 ;
  RECT 38.220 763.280 41.760 764.400 ;
 END
 PORT
  LAYER metal4 ;
  RECT 29.540 763.280 33.080 764.400 ;
  LAYER metal3 ;
  RECT 29.540 763.280 33.080 764.400 ;
  LAYER metal2 ;
  RECT 29.540 763.280 33.080 764.400 ;
  LAYER metal1 ;
  RECT 29.540 763.280 33.080 764.400 ;
 END
 PORT
  LAYER metal4 ;
  RECT 20.860 763.280 24.400 764.400 ;
  LAYER metal3 ;
  RECT 20.860 763.280 24.400 764.400 ;
  LAYER metal2 ;
  RECT 20.860 763.280 24.400 764.400 ;
  LAYER metal1 ;
  RECT 20.860 763.280 24.400 764.400 ;
 END
 PORT
  LAYER metal4 ;
  RECT 12.180 763.280 15.720 764.400 ;
  LAYER metal3 ;
  RECT 12.180 763.280 15.720 764.400 ;
  LAYER metal2 ;
  RECT 12.180 763.280 15.720 764.400 ;
  LAYER metal1 ;
  RECT 12.180 763.280 15.720 764.400 ;
 END
 PORT
  LAYER metal4 ;
  RECT 317.840 0.000 321.380 1.120 ;
  LAYER metal3 ;
  RECT 317.840 0.000 321.380 1.120 ;
  LAYER metal2 ;
  RECT 317.840 0.000 321.380 1.120 ;
  LAYER metal1 ;
  RECT 317.840 0.000 321.380 1.120 ;
 END
 PORT
  LAYER metal4 ;
  RECT 296.140 0.000 299.680 1.120 ;
  LAYER metal3 ;
  RECT 296.140 0.000 299.680 1.120 ;
  LAYER metal2 ;
  RECT 296.140 0.000 299.680 1.120 ;
  LAYER metal1 ;
  RECT 296.140 0.000 299.680 1.120 ;
 END
 PORT
  LAYER metal4 ;
  RECT 274.440 0.000 277.980 1.120 ;
  LAYER metal3 ;
  RECT 274.440 0.000 277.980 1.120 ;
  LAYER metal2 ;
  RECT 274.440 0.000 277.980 1.120 ;
  LAYER metal1 ;
  RECT 274.440 0.000 277.980 1.120 ;
 END
 PORT
  LAYER metal4 ;
  RECT 247.780 0.000 251.320 1.120 ;
  LAYER metal3 ;
  RECT 247.780 0.000 251.320 1.120 ;
  LAYER metal2 ;
  RECT 247.780 0.000 251.320 1.120 ;
  LAYER metal1 ;
  RECT 247.780 0.000 251.320 1.120 ;
 END
 PORT
  LAYER metal4 ;
  RECT 231.040 0.000 234.580 1.120 ;
  LAYER metal3 ;
  RECT 231.040 0.000 234.580 1.120 ;
  LAYER metal2 ;
  RECT 231.040 0.000 234.580 1.120 ;
  LAYER metal1 ;
  RECT 231.040 0.000 234.580 1.120 ;
 END
 PORT
  LAYER metal4 ;
  RECT 126.260 0.000 129.800 1.120 ;
  LAYER metal3 ;
  RECT 126.260 0.000 129.800 1.120 ;
  LAYER metal2 ;
  RECT 126.260 0.000 129.800 1.120 ;
  LAYER metal1 ;
  RECT 126.260 0.000 129.800 1.120 ;
 END
 PORT
  LAYER metal4 ;
  RECT 113.860 0.000 117.400 1.120 ;
  LAYER metal3 ;
  RECT 113.860 0.000 117.400 1.120 ;
  LAYER metal2 ;
  RECT 113.860 0.000 117.400 1.120 ;
  LAYER metal1 ;
  RECT 113.860 0.000 117.400 1.120 ;
 END
 PORT
  LAYER metal4 ;
  RECT 92.160 0.000 95.700 1.120 ;
  LAYER metal3 ;
  RECT 92.160 0.000 95.700 1.120 ;
  LAYER metal2 ;
  RECT 92.160 0.000 95.700 1.120 ;
  LAYER metal1 ;
  RECT 92.160 0.000 95.700 1.120 ;
 END
 PORT
  LAYER metal4 ;
  RECT 70.460 0.000 74.000 1.120 ;
  LAYER metal3 ;
  RECT 70.460 0.000 74.000 1.120 ;
  LAYER metal2 ;
  RECT 70.460 0.000 74.000 1.120 ;
  LAYER metal1 ;
  RECT 70.460 0.000 74.000 1.120 ;
 END
 PORT
  LAYER metal4 ;
  RECT 43.800 0.000 47.340 1.120 ;
  LAYER metal3 ;
  RECT 43.800 0.000 47.340 1.120 ;
  LAYER metal2 ;
  RECT 43.800 0.000 47.340 1.120 ;
  LAYER metal1 ;
  RECT 43.800 0.000 47.340 1.120 ;
 END
 PORT
  LAYER metal4 ;
  RECT 27.060 0.000 30.600 1.120 ;
  LAYER metal3 ;
  RECT 27.060 0.000 30.600 1.120 ;
  LAYER metal2 ;
  RECT 27.060 0.000 30.600 1.120 ;
  LAYER metal1 ;
  RECT 27.060 0.000 30.600 1.120 ;
 END
END GND
PIN DO15
  DIRECTION OUTPUT ;
  CAPACITANCE 0.031 ;
 PORT
  LAYER metal4 ;
  RECT 323.700 0.000 324.820 1.120 ;
  LAYER metal3 ;
  RECT 323.700 0.000 324.820 1.120 ;
  LAYER metal2 ;
  RECT 323.700 0.000 324.820 1.120 ;
  LAYER metal1 ;
  RECT 323.700 0.000 324.820 1.120 ;
 END
END DO15
PIN DI15
  DIRECTION INPUT ;
  CAPACITANCE 0.012 ;
 PORT
  LAYER metal4 ;
  RECT 315.640 0.000 316.760 1.120 ;
  LAYER metal3 ;
  RECT 315.640 0.000 316.760 1.120 ;
  LAYER metal2 ;
  RECT 315.640 0.000 316.760 1.120 ;
  LAYER metal1 ;
  RECT 315.640 0.000 316.760 1.120 ;
 END
END DI15
PIN DO14
  DIRECTION OUTPUT ;
  CAPACITANCE 0.031 ;
 PORT
  LAYER metal4 ;
  RECT 310.680 0.000 311.800 1.120 ;
  LAYER metal3 ;
  RECT 310.680 0.000 311.800 1.120 ;
  LAYER metal2 ;
  RECT 310.680 0.000 311.800 1.120 ;
  LAYER metal1 ;
  RECT 310.680 0.000 311.800 1.120 ;
 END
END DO14
PIN DI14
  DIRECTION INPUT ;
  CAPACITANCE 0.012 ;
 PORT
  LAYER metal4 ;
  RECT 302.000 0.000 303.120 1.120 ;
  LAYER metal3 ;
  RECT 302.000 0.000 303.120 1.120 ;
  LAYER metal2 ;
  RECT 302.000 0.000 303.120 1.120 ;
  LAYER metal1 ;
  RECT 302.000 0.000 303.120 1.120 ;
 END
END DI14
PIN DO13
  DIRECTION OUTPUT ;
  CAPACITANCE 0.031 ;
 PORT
  LAYER metal4 ;
  RECT 293.940 0.000 295.060 1.120 ;
  LAYER metal3 ;
  RECT 293.940 0.000 295.060 1.120 ;
  LAYER metal2 ;
  RECT 293.940 0.000 295.060 1.120 ;
  LAYER metal1 ;
  RECT 293.940 0.000 295.060 1.120 ;
 END
END DO13
PIN DI13
  DIRECTION INPUT ;
  CAPACITANCE 0.012 ;
 PORT
  LAYER metal4 ;
  RECT 285.260 0.000 286.380 1.120 ;
  LAYER metal3 ;
  RECT 285.260 0.000 286.380 1.120 ;
  LAYER metal2 ;
  RECT 285.260 0.000 286.380 1.120 ;
  LAYER metal1 ;
  RECT 285.260 0.000 286.380 1.120 ;
 END
END DI13
PIN DO12
  DIRECTION OUTPUT ;
  CAPACITANCE 0.031 ;
 PORT
  LAYER metal4 ;
  RECT 280.920 0.000 282.040 1.120 ;
  LAYER metal3 ;
  RECT 280.920 0.000 282.040 1.120 ;
  LAYER metal2 ;
  RECT 280.920 0.000 282.040 1.120 ;
  LAYER metal1 ;
  RECT 280.920 0.000 282.040 1.120 ;
 END
END DO12
PIN DI12
  DIRECTION INPUT ;
  CAPACITANCE 0.012 ;
 PORT
  LAYER metal4 ;
  RECT 272.240 0.000 273.360 1.120 ;
  LAYER metal3 ;
  RECT 272.240 0.000 273.360 1.120 ;
  LAYER metal2 ;
  RECT 272.240 0.000 273.360 1.120 ;
  LAYER metal1 ;
  RECT 272.240 0.000 273.360 1.120 ;
 END
END DI12
PIN DO11
  DIRECTION OUTPUT ;
  CAPACITANCE 0.031 ;
 PORT
  LAYER metal4 ;
  RECT 267.280 0.000 268.400 1.120 ;
  LAYER metal3 ;
  RECT 267.280 0.000 268.400 1.120 ;
  LAYER metal2 ;
  RECT 267.280 0.000 268.400 1.120 ;
  LAYER metal1 ;
  RECT 267.280 0.000 268.400 1.120 ;
 END
END DO11
PIN DI11
  DIRECTION INPUT ;
  CAPACITANCE 0.012 ;
 PORT
  LAYER metal4 ;
  RECT 259.220 0.000 260.340 1.120 ;
  LAYER metal3 ;
  RECT 259.220 0.000 260.340 1.120 ;
  LAYER metal2 ;
  RECT 259.220 0.000 260.340 1.120 ;
  LAYER metal1 ;
  RECT 259.220 0.000 260.340 1.120 ;
 END
END DI11
PIN DO10
  DIRECTION OUTPUT ;
  CAPACITANCE 0.031 ;
 PORT
  LAYER metal4 ;
  RECT 254.260 0.000 255.380 1.120 ;
  LAYER metal3 ;
  RECT 254.260 0.000 255.380 1.120 ;
  LAYER metal2 ;
  RECT 254.260 0.000 255.380 1.120 ;
  LAYER metal1 ;
  RECT 254.260 0.000 255.380 1.120 ;
 END
END DO10
PIN DI10
  DIRECTION INPUT ;
  CAPACITANCE 0.012 ;
 PORT
  LAYER metal4 ;
  RECT 245.580 0.000 246.700 1.120 ;
  LAYER metal3 ;
  RECT 245.580 0.000 246.700 1.120 ;
  LAYER metal2 ;
  RECT 245.580 0.000 246.700 1.120 ;
  LAYER metal1 ;
  RECT 245.580 0.000 246.700 1.120 ;
 END
END DI10
PIN DO9
  DIRECTION OUTPUT ;
  CAPACITANCE 0.031 ;
 PORT
  LAYER metal4 ;
  RECT 237.520 0.000 238.640 1.120 ;
  LAYER metal3 ;
  RECT 237.520 0.000 238.640 1.120 ;
  LAYER metal2 ;
  RECT 237.520 0.000 238.640 1.120 ;
  LAYER metal1 ;
  RECT 237.520 0.000 238.640 1.120 ;
 END
END DO9
PIN DI9
  DIRECTION INPUT ;
  CAPACITANCE 0.012 ;
 PORT
  LAYER metal4 ;
  RECT 228.840 0.000 229.960 1.120 ;
  LAYER metal3 ;
  RECT 228.840 0.000 229.960 1.120 ;
  LAYER metal2 ;
  RECT 228.840 0.000 229.960 1.120 ;
  LAYER metal1 ;
  RECT 228.840 0.000 229.960 1.120 ;
 END
END DI9
PIN DO8
  DIRECTION OUTPUT ;
  CAPACITANCE 0.031 ;
 PORT
  LAYER metal4 ;
  RECT 223.880 0.000 225.000 1.120 ;
  LAYER metal3 ;
  RECT 223.880 0.000 225.000 1.120 ;
  LAYER metal2 ;
  RECT 223.880 0.000 225.000 1.120 ;
  LAYER metal1 ;
  RECT 223.880 0.000 225.000 1.120 ;
 END
END DO8
PIN DI8
  DIRECTION INPUT ;
  CAPACITANCE 0.012 ;
 PORT
  LAYER metal4 ;
  RECT 215.820 0.000 216.940 1.120 ;
  LAYER metal3 ;
  RECT 215.820 0.000 216.940 1.120 ;
  LAYER metal2 ;
  RECT 215.820 0.000 216.940 1.120 ;
  LAYER metal1 ;
  RECT 215.820 0.000 216.940 1.120 ;
 END
END DI8
PIN A1
  DIRECTION INPUT ;
  CAPACITANCE 0.027 ;
 PORT
  LAYER metal4 ;
  RECT 210.240 0.000 211.360 1.120 ;
  LAYER metal3 ;
  RECT 210.240 0.000 211.360 1.120 ;
  LAYER metal2 ;
  RECT 210.240 0.000 211.360 1.120 ;
  LAYER metal1 ;
  RECT 210.240 0.000 211.360 1.120 ;
 END
END A1
PIN WEB
  DIRECTION INPUT ;
  CAPACITANCE 0.011 ;
 PORT
  LAYER metal4 ;
  RECT 208.380 0.000 209.500 1.120 ;
  LAYER metal3 ;
  RECT 208.380 0.000 209.500 1.120 ;
  LAYER metal2 ;
  RECT 208.380 0.000 209.500 1.120 ;
  LAYER metal1 ;
  RECT 208.380 0.000 209.500 1.120 ;
 END
END WEB
PIN OE
  DIRECTION INPUT ;
  CAPACITANCE 0.033 ;
 PORT
  LAYER metal4 ;
  RECT 203.420 0.000 204.540 1.120 ;
  LAYER metal3 ;
  RECT 203.420 0.000 204.540 1.120 ;
  LAYER metal2 ;
  RECT 203.420 0.000 204.540 1.120 ;
  LAYER metal1 ;
  RECT 203.420 0.000 204.540 1.120 ;
 END
END OE
PIN CS
  DIRECTION INPUT ;
  CAPACITANCE 0.123 ;
 PORT
  LAYER metal4 ;
  RECT 201.560 0.000 202.680 1.120 ;
  LAYER metal3 ;
  RECT 201.560 0.000 202.680 1.120 ;
  LAYER metal2 ;
  RECT 201.560 0.000 202.680 1.120 ;
  LAYER metal1 ;
  RECT 201.560 0.000 202.680 1.120 ;
 END
END CS
PIN A2
  DIRECTION INPUT ;
  CAPACITANCE 0.027 ;
 PORT
  LAYER metal4 ;
  RECT 179.860 0.000 180.980 1.120 ;
  LAYER metal3 ;
  RECT 179.860 0.000 180.980 1.120 ;
  LAYER metal2 ;
  RECT 179.860 0.000 180.980 1.120 ;
  LAYER metal1 ;
  RECT 179.860 0.000 180.980 1.120 ;
 END
END A2
PIN CK
  DIRECTION INPUT ;
  CAPACITANCE 0.063 ;
 PORT
  LAYER metal4 ;
  RECT 176.760 0.000 177.880 1.120 ;
  LAYER metal3 ;
  RECT 176.760 0.000 177.880 1.120 ;
  LAYER metal2 ;
  RECT 176.760 0.000 177.880 1.120 ;
  LAYER metal1 ;
  RECT 176.760 0.000 177.880 1.120 ;
 END
END CK
PIN A0
  DIRECTION INPUT ;
  CAPACITANCE 0.027 ;
 PORT
  LAYER metal4 ;
  RECT 174.900 0.000 176.020 1.120 ;
  LAYER metal3 ;
  RECT 174.900 0.000 176.020 1.120 ;
  LAYER metal2 ;
  RECT 174.900 0.000 176.020 1.120 ;
  LAYER metal1 ;
  RECT 174.900 0.000 176.020 1.120 ;
 END
END A0
PIN A3
  DIRECTION INPUT ;
  CAPACITANCE 0.027 ;
 PORT
  LAYER metal4 ;
  RECT 170.560 0.000 171.680 1.120 ;
  LAYER metal3 ;
  RECT 170.560 0.000 171.680 1.120 ;
  LAYER metal2 ;
  RECT 170.560 0.000 171.680 1.120 ;
  LAYER metal1 ;
  RECT 170.560 0.000 171.680 1.120 ;
 END
END A3
PIN A4
  DIRECTION INPUT ;
  CAPACITANCE 0.027 ;
 PORT
  LAYER metal4 ;
  RECT 163.120 0.000 164.240 1.120 ;
  LAYER metal3 ;
  RECT 163.120 0.000 164.240 1.120 ;
  LAYER metal2 ;
  RECT 163.120 0.000 164.240 1.120 ;
  LAYER metal1 ;
  RECT 163.120 0.000 164.240 1.120 ;
 END
END A4
PIN A5
  DIRECTION INPUT ;
  CAPACITANCE 0.027 ;
 PORT
  LAYER metal4 ;
  RECT 160.020 0.000 161.140 1.120 ;
  LAYER metal3 ;
  RECT 160.020 0.000 161.140 1.120 ;
  LAYER metal2 ;
  RECT 160.020 0.000 161.140 1.120 ;
  LAYER metal1 ;
  RECT 160.020 0.000 161.140 1.120 ;
 END
END A5
PIN A6
  DIRECTION INPUT ;
  CAPACITANCE 0.027 ;
 PORT
  LAYER metal4 ;
  RECT 151.960 0.000 153.080 1.120 ;
  LAYER metal3 ;
  RECT 151.960 0.000 153.080 1.120 ;
  LAYER metal2 ;
  RECT 151.960 0.000 153.080 1.120 ;
  LAYER metal1 ;
  RECT 151.960 0.000 153.080 1.120 ;
 END
END A6
PIN A7
  DIRECTION INPUT ;
  CAPACITANCE 0.027 ;
 PORT
  LAYER metal4 ;
  RECT 148.860 0.000 149.980 1.120 ;
  LAYER metal3 ;
  RECT 148.860 0.000 149.980 1.120 ;
  LAYER metal2 ;
  RECT 148.860 0.000 149.980 1.120 ;
  LAYER metal1 ;
  RECT 148.860 0.000 149.980 1.120 ;
 END
END A7
PIN A8
  DIRECTION INPUT ;
  CAPACITANCE 0.027 ;
 PORT
  LAYER metal4 ;
  RECT 141.420 0.000 142.540 1.120 ;
  LAYER metal3 ;
  RECT 141.420 0.000 142.540 1.120 ;
  LAYER metal2 ;
  RECT 141.420 0.000 142.540 1.120 ;
  LAYER metal1 ;
  RECT 141.420 0.000 142.540 1.120 ;
 END
END A8
PIN A9
  DIRECTION INPUT ;
  CAPACITANCE 0.027 ;
 PORT
  LAYER metal4 ;
  RECT 138.320 0.000 139.440 1.120 ;
  LAYER metal3 ;
  RECT 138.320 0.000 139.440 1.120 ;
  LAYER metal2 ;
  RECT 138.320 0.000 139.440 1.120 ;
  LAYER metal1 ;
  RECT 138.320 0.000 139.440 1.120 ;
 END
END A9
PIN A10
  DIRECTION INPUT ;
  CAPACITANCE 0.027 ;
 PORT
  LAYER metal4 ;
  RECT 130.880 0.000 132.000 1.120 ;
  LAYER metal3 ;
  RECT 130.880 0.000 132.000 1.120 ;
  LAYER metal2 ;
  RECT 130.880 0.000 132.000 1.120 ;
  LAYER metal1 ;
  RECT 130.880 0.000 132.000 1.120 ;
 END
END A10
PIN DO7
  DIRECTION OUTPUT ;
  CAPACITANCE 0.031 ;
 PORT
  LAYER metal4 ;
  RECT 119.720 0.000 120.840 1.120 ;
  LAYER metal3 ;
  RECT 119.720 0.000 120.840 1.120 ;
  LAYER metal2 ;
  RECT 119.720 0.000 120.840 1.120 ;
  LAYER metal1 ;
  RECT 119.720 0.000 120.840 1.120 ;
 END
END DO7
PIN DI7
  DIRECTION INPUT ;
  CAPACITANCE 0.012 ;
 PORT
  LAYER metal4 ;
  RECT 111.660 0.000 112.780 1.120 ;
  LAYER metal3 ;
  RECT 111.660 0.000 112.780 1.120 ;
  LAYER metal2 ;
  RECT 111.660 0.000 112.780 1.120 ;
  LAYER metal1 ;
  RECT 111.660 0.000 112.780 1.120 ;
 END
END DI7
PIN DO6
  DIRECTION OUTPUT ;
  CAPACITANCE 0.031 ;
 PORT
  LAYER metal4 ;
  RECT 106.700 0.000 107.820 1.120 ;
  LAYER metal3 ;
  RECT 106.700 0.000 107.820 1.120 ;
  LAYER metal2 ;
  RECT 106.700 0.000 107.820 1.120 ;
  LAYER metal1 ;
  RECT 106.700 0.000 107.820 1.120 ;
 END
END DO6
PIN DI6
  DIRECTION INPUT ;
  CAPACITANCE 0.012 ;
 PORT
  LAYER metal4 ;
  RECT 98.020 0.000 99.140 1.120 ;
  LAYER metal3 ;
  RECT 98.020 0.000 99.140 1.120 ;
  LAYER metal2 ;
  RECT 98.020 0.000 99.140 1.120 ;
  LAYER metal1 ;
  RECT 98.020 0.000 99.140 1.120 ;
 END
END DI6
PIN DO5
  DIRECTION OUTPUT ;
  CAPACITANCE 0.031 ;
 PORT
  LAYER metal4 ;
  RECT 89.960 0.000 91.080 1.120 ;
  LAYER metal3 ;
  RECT 89.960 0.000 91.080 1.120 ;
  LAYER metal2 ;
  RECT 89.960 0.000 91.080 1.120 ;
  LAYER metal1 ;
  RECT 89.960 0.000 91.080 1.120 ;
 END
END DO5
PIN DI5
  DIRECTION INPUT ;
  CAPACITANCE 0.012 ;
 PORT
  LAYER metal4 ;
  RECT 81.280 0.000 82.400 1.120 ;
  LAYER metal3 ;
  RECT 81.280 0.000 82.400 1.120 ;
  LAYER metal2 ;
  RECT 81.280 0.000 82.400 1.120 ;
  LAYER metal1 ;
  RECT 81.280 0.000 82.400 1.120 ;
 END
END DI5
PIN DO4
  DIRECTION OUTPUT ;
  CAPACITANCE 0.031 ;
 PORT
  LAYER metal4 ;
  RECT 76.320 0.000 77.440 1.120 ;
  LAYER metal3 ;
  RECT 76.320 0.000 77.440 1.120 ;
  LAYER metal2 ;
  RECT 76.320 0.000 77.440 1.120 ;
  LAYER metal1 ;
  RECT 76.320 0.000 77.440 1.120 ;
 END
END DO4
PIN DI4
  DIRECTION INPUT ;
  CAPACITANCE 0.012 ;
 PORT
  LAYER metal4 ;
  RECT 68.260 0.000 69.380 1.120 ;
  LAYER metal3 ;
  RECT 68.260 0.000 69.380 1.120 ;
  LAYER metal2 ;
  RECT 68.260 0.000 69.380 1.120 ;
  LAYER metal1 ;
  RECT 68.260 0.000 69.380 1.120 ;
 END
END DI4
PIN DO3
  DIRECTION OUTPUT ;
  CAPACITANCE 0.031 ;
 PORT
  LAYER metal4 ;
  RECT 63.300 0.000 64.420 1.120 ;
  LAYER metal3 ;
  RECT 63.300 0.000 64.420 1.120 ;
  LAYER metal2 ;
  RECT 63.300 0.000 64.420 1.120 ;
  LAYER metal1 ;
  RECT 63.300 0.000 64.420 1.120 ;
 END
END DO3
PIN DI3
  DIRECTION INPUT ;
  CAPACITANCE 0.012 ;
 PORT
  LAYER metal4 ;
  RECT 54.620 0.000 55.740 1.120 ;
  LAYER metal3 ;
  RECT 54.620 0.000 55.740 1.120 ;
  LAYER metal2 ;
  RECT 54.620 0.000 55.740 1.120 ;
  LAYER metal1 ;
  RECT 54.620 0.000 55.740 1.120 ;
 END
END DI3
PIN DO2
  DIRECTION OUTPUT ;
  CAPACITANCE 0.031 ;
 PORT
  LAYER metal4 ;
  RECT 50.280 0.000 51.400 1.120 ;
  LAYER metal3 ;
  RECT 50.280 0.000 51.400 1.120 ;
  LAYER metal2 ;
  RECT 50.280 0.000 51.400 1.120 ;
  LAYER metal1 ;
  RECT 50.280 0.000 51.400 1.120 ;
 END
END DO2
PIN DI2
  DIRECTION INPUT ;
  CAPACITANCE 0.012 ;
 PORT
  LAYER metal4 ;
  RECT 41.600 0.000 42.720 1.120 ;
  LAYER metal3 ;
  RECT 41.600 0.000 42.720 1.120 ;
  LAYER metal2 ;
  RECT 41.600 0.000 42.720 1.120 ;
  LAYER metal1 ;
  RECT 41.600 0.000 42.720 1.120 ;
 END
END DI2
PIN DO1
  DIRECTION OUTPUT ;
  CAPACITANCE 0.031 ;
 PORT
  LAYER metal4 ;
  RECT 33.540 0.000 34.660 1.120 ;
  LAYER metal3 ;
  RECT 33.540 0.000 34.660 1.120 ;
  LAYER metal2 ;
  RECT 33.540 0.000 34.660 1.120 ;
  LAYER metal1 ;
  RECT 33.540 0.000 34.660 1.120 ;
 END
END DO1
PIN DI1
  DIRECTION INPUT ;
  CAPACITANCE 0.012 ;
 PORT
  LAYER metal4 ;
  RECT 24.860 0.000 25.980 1.120 ;
  LAYER metal3 ;
  RECT 24.860 0.000 25.980 1.120 ;
  LAYER metal2 ;
  RECT 24.860 0.000 25.980 1.120 ;
  LAYER metal1 ;
  RECT 24.860 0.000 25.980 1.120 ;
 END
END DI1
PIN DO0
  DIRECTION OUTPUT ;
  CAPACITANCE 0.031 ;
 PORT
  LAYER metal4 ;
  RECT 19.900 0.000 21.020 1.120 ;
  LAYER metal3 ;
  RECT 19.900 0.000 21.020 1.120 ;
  LAYER metal2 ;
  RECT 19.900 0.000 21.020 1.120 ;
  LAYER metal1 ;
  RECT 19.900 0.000 21.020 1.120 ;
 END
END DO0
PIN DI0
  DIRECTION INPUT ;
  CAPACITANCE 0.012 ;
 PORT
  LAYER metal4 ;
  RECT 11.840 0.000 12.960 1.120 ;
  LAYER metal3 ;
  RECT 11.840 0.000 12.960 1.120 ;
  LAYER metal2 ;
  RECT 11.840 0.000 12.960 1.120 ;
  LAYER metal1 ;
  RECT 11.840 0.000 12.960 1.120 ;
 END
END DI0
OBS
  LAYER metal1 SPACING 0.280 ;
  RECT 0.000 0.140 337.280 764.400 ;
  LAYER metal2 SPACING 0.320 ;
  RECT 0.000 0.140 337.280 764.400 ;
  LAYER metal3 SPACING 0.320 ;
  RECT 0.000 0.140 337.280 764.400 ;
  LAYER metal4 SPACING 0.600 ;
  RECT 0.000 0.140 337.280 764.400 ;
  LAYER via ;
  RECT 0.000 0.140 337.280 764.400 ;
  LAYER via2 ;
  RECT 0.000 0.140 337.280 764.400 ;
  LAYER via3 ;
  RECT 0.000 0.140 337.280 764.400 ;
END
END SUMA180_2048X16X1BM1
END LIBRARY



